VERSION 5.8 ;
BUSBITCHARS "[]" ;
DIVIDERCHAR "/" ;
UNITS
    DATABASE MICRONS 1000 ;
END UNITS

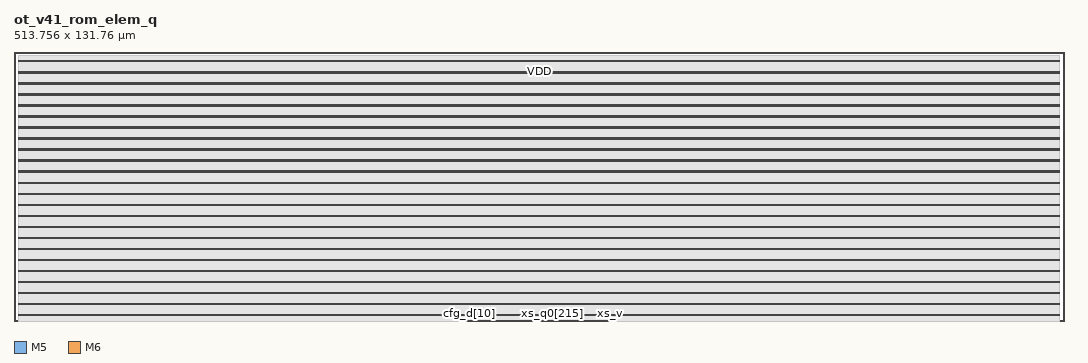
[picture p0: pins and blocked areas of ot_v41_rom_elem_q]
MACRO ot_v41_rom_elem_q
  FOREIGN ot_v41_rom_elem_q 0 0 ;
  CLASS BLOCK ;
  SIZE 513.756 BY 131.76 ;
  PIN busy
    DIRECTION OUTPUT ;
    USE SIGNAL ;
    PORT
      LAYER M5 ;
        RECT  221.568 0 221.592 0.084 ;
    END
  END busy
  PIN cfg_a[0]
    DIRECTION INPUT ;
    USE SIGNAL ;
    PORT
      LAYER M5 ;
        RECT  221.664 0 221.688 0.084 ;
    END
  END cfg_a[0]
  PIN cfg_a[1]
    DIRECTION INPUT ;
    USE SIGNAL ;
    PORT
      LAYER M5 ;
        RECT  221.76 0 221.784 0.084 ;
    END
  END cfg_a[1]
  PIN cfg_a[2]
    DIRECTION INPUT ;
    USE SIGNAL ;
    PORT
      LAYER M5 ;
        RECT  221.856 0 221.88 0.084 ;
    END
  END cfg_a[2]
  PIN cfg_a[3]
    DIRECTION INPUT ;
    USE SIGNAL ;
    PORT
      LAYER M5 ;
        RECT  221.952 0 221.976 0.084 ;
    END
  END cfg_a[3]
  PIN cfg_a[4]
    DIRECTION INPUT ;
    USE SIGNAL ;
    PORT
      LAYER M5 ;
        RECT  222.048 0 222.072 0.084 ;
    END
  END cfg_a[4]
  PIN cfg_d[0]
    DIRECTION INPUT ;
    USE SIGNAL ;
    PORT
      LAYER M5 ;
        RECT  222.144 0 222.168 0.084 ;
    END
  END cfg_d[0]
  PIN cfg_d[10]
    DIRECTION INPUT ;
    USE SIGNAL ;
    PORT
      LAYER M5 ;
        RECT  223.104 0 223.128 0.084 ;
    END
  END cfg_d[10]
  PIN cfg_d[11]
    DIRECTION INPUT ;
    USE SIGNAL ;
    PORT
      LAYER M5 ;
        RECT  223.2 0 223.224 0.084 ;
    END
  END cfg_d[11]
  PIN cfg_d[12]
    DIRECTION INPUT ;
    USE SIGNAL ;
    PORT
      LAYER M5 ;
        RECT  223.296 0 223.32 0.084 ;
    END
  END cfg_d[12]
  PIN cfg_d[13]
    DIRECTION INPUT ;
    USE SIGNAL ;
    PORT
      LAYER M5 ;
        RECT  223.392 0 223.416 0.084 ;
    END
  END cfg_d[13]
  PIN cfg_d[14]
    DIRECTION INPUT ;
    USE SIGNAL ;
    PORT
      LAYER M5 ;
        RECT  223.488 0 223.512 0.084 ;
    END
  END cfg_d[14]
  PIN cfg_d[15]
    DIRECTION INPUT ;
    USE SIGNAL ;
    PORT
      LAYER M5 ;
        RECT  223.584 0 223.608 0.084 ;
    END
  END cfg_d[15]
  PIN cfg_d[16]
    DIRECTION INPUT ;
    USE SIGNAL ;
    PORT
      LAYER M5 ;
        RECT  223.68 0 223.704 0.084 ;
    END
  END cfg_d[16]
  PIN cfg_d[17]
    DIRECTION INPUT ;
    USE SIGNAL ;
    PORT
      LAYER M5 ;
        RECT  223.776 0 223.8 0.084 ;
    END
  END cfg_d[17]
  PIN cfg_d[18]
    DIRECTION INPUT ;
    USE SIGNAL ;
    PORT
      LAYER M5 ;
        RECT  223.872 0 223.896 0.084 ;
    END
  END cfg_d[18]
  PIN cfg_d[19]
    DIRECTION INPUT ;
    USE SIGNAL ;
    PORT
      LAYER M5 ;
        RECT  223.968 0 223.992 0.084 ;
    END
  END cfg_d[19]
  PIN cfg_d[1]
    DIRECTION INPUT ;
    USE SIGNAL ;
    PORT
      LAYER M5 ;
        RECT  222.24 0 222.264 0.084 ;
    END
  END cfg_d[1]
  PIN cfg_d[20]
    DIRECTION INPUT ;
    USE SIGNAL ;
    PORT
      LAYER M5 ;
        RECT  224.064 0 224.088 0.084 ;
    END
  END cfg_d[20]
  PIN cfg_d[21]
    DIRECTION INPUT ;
    USE SIGNAL ;
    PORT
      LAYER M5 ;
        RECT  224.16 0 224.184 0.084 ;
    END
  END cfg_d[21]
  PIN cfg_d[22]
    DIRECTION INPUT ;
    USE SIGNAL ;
    PORT
      LAYER M5 ;
        RECT  224.256 0 224.28 0.084 ;
    END
  END cfg_d[22]
  PIN cfg_d[23]
    DIRECTION INPUT ;
    USE SIGNAL ;
    PORT
      LAYER M5 ;
        RECT  224.352 0 224.376 0.084 ;
    END
  END cfg_d[23]
  PIN cfg_d[24]
    DIRECTION INPUT ;
    USE SIGNAL ;
    PORT
      LAYER M5 ;
        RECT  224.448 0 224.472 0.084 ;
    END
  END cfg_d[24]
  PIN cfg_d[25]
    DIRECTION INPUT ;
    USE SIGNAL ;
    PORT
      LAYER M5 ;
        RECT  224.544 0 224.568 0.084 ;
    END
  END cfg_d[25]
  PIN cfg_d[26]
    DIRECTION INPUT ;
    USE SIGNAL ;
    PORT
      LAYER M5 ;
        RECT  224.64 0 224.664 0.084 ;
    END
  END cfg_d[26]
  PIN cfg_d[27]
    DIRECTION INPUT ;
    USE SIGNAL ;
    PORT
      LAYER M5 ;
        RECT  224.736 0 224.76 0.084 ;
    END
  END cfg_d[27]
  PIN cfg_d[28]
    DIRECTION INPUT ;
    USE SIGNAL ;
    PORT
      LAYER M5 ;
        RECT  224.832 0 224.856 0.084 ;
    END
  END cfg_d[28]
  PIN cfg_d[29]
    DIRECTION INPUT ;
    USE SIGNAL ;
    PORT
      LAYER M5 ;
        RECT  224.928 0 224.952 0.084 ;
    END
  END cfg_d[29]
  PIN cfg_d[2]
    DIRECTION INPUT ;
    USE SIGNAL ;
    PORT
      LAYER M5 ;
        RECT  222.336 0 222.36 0.084 ;
    END
  END cfg_d[2]
  PIN cfg_d[30]
    DIRECTION INPUT ;
    USE SIGNAL ;
    PORT
      LAYER M5 ;
        RECT  225.024 0 225.048 0.084 ;
    END
  END cfg_d[30]
  PIN cfg_d[31]
    DIRECTION INPUT ;
    USE SIGNAL ;
    PORT
      LAYER M5 ;
        RECT  225.12 0 225.144 0.084 ;
    END
  END cfg_d[31]
  PIN cfg_d[32]
    DIRECTION INPUT ;
    USE SIGNAL ;
    PORT
      LAYER M5 ;
        RECT  225.216 0 225.24 0.084 ;
    END
  END cfg_d[32]
  PIN cfg_d[33]
    DIRECTION INPUT ;
    USE SIGNAL ;
    PORT
      LAYER M5 ;
        RECT  225.312 0 225.336 0.084 ;
    END
  END cfg_d[33]
  PIN cfg_d[34]
    DIRECTION INPUT ;
    USE SIGNAL ;
    PORT
      LAYER M5 ;
        RECT  225.408 0 225.432 0.084 ;
    END
  END cfg_d[34]
  PIN cfg_d[35]
    DIRECTION INPUT ;
    USE SIGNAL ;
    PORT
      LAYER M5 ;
        RECT  225.504 0 225.528 0.084 ;
    END
  END cfg_d[35]
  PIN cfg_d[36]
    DIRECTION INPUT ;
    USE SIGNAL ;
    PORT
      LAYER M5 ;
        RECT  225.6 0 225.624 0.084 ;
    END
  END cfg_d[36]
  PIN cfg_d[37]
    DIRECTION INPUT ;
    USE SIGNAL ;
    PORT
      LAYER M5 ;
        RECT  225.696 0 225.72 0.084 ;
    END
  END cfg_d[37]
  PIN cfg_d[38]
    DIRECTION INPUT ;
    USE SIGNAL ;
    PORT
      LAYER M5 ;
        RECT  225.792 0 225.816 0.084 ;
    END
  END cfg_d[38]
  PIN cfg_d[39]
    DIRECTION INPUT ;
    USE SIGNAL ;
    PORT
      LAYER M5 ;
        RECT  225.888 0 225.912 0.084 ;
    END
  END cfg_d[39]
  PIN cfg_d[3]
    DIRECTION INPUT ;
    USE SIGNAL ;
    PORT
      LAYER M5 ;
        RECT  222.432 0 222.456 0.084 ;
    END
  END cfg_d[3]
  PIN cfg_d[40]
    DIRECTION INPUT ;
    USE SIGNAL ;
    PORT
      LAYER M5 ;
        RECT  225.984 0 226.008 0.084 ;
    END
  END cfg_d[40]
  PIN cfg_d[41]
    DIRECTION INPUT ;
    USE SIGNAL ;
    PORT
      LAYER M5 ;
        RECT  226.08 0 226.104 0.084 ;
    END
  END cfg_d[41]
  PIN cfg_d[42]
    DIRECTION INPUT ;
    USE SIGNAL ;
    PORT
      LAYER M5 ;
        RECT  226.176 0 226.2 0.084 ;
    END
  END cfg_d[42]
  PIN cfg_d[43]
    DIRECTION INPUT ;
    USE SIGNAL ;
    PORT
      LAYER M5 ;
        RECT  226.272 0 226.296 0.084 ;
    END
  END cfg_d[43]
  PIN cfg_d[44]
    DIRECTION INPUT ;
    USE SIGNAL ;
    PORT
      LAYER M5 ;
        RECT  226.368 0 226.392 0.084 ;
    END
  END cfg_d[44]
  PIN cfg_d[45]
    DIRECTION INPUT ;
    USE SIGNAL ;
    PORT
      LAYER M5 ;
        RECT  226.464 0 226.488 0.084 ;
    END
  END cfg_d[45]
  PIN cfg_d[46]
    DIRECTION INPUT ;
    USE SIGNAL ;
    PORT
      LAYER M5 ;
        RECT  226.56 0 226.584 0.084 ;
    END
  END cfg_d[46]
  PIN cfg_d[47]
    DIRECTION INPUT ;
    USE SIGNAL ;
    PORT
      LAYER M5 ;
        RECT  226.656 0 226.68 0.084 ;
    END
  END cfg_d[47]
  PIN cfg_d[4]
    DIRECTION INPUT ;
    USE SIGNAL ;
    PORT
      LAYER M5 ;
        RECT  222.528 0 222.552 0.084 ;
    END
  END cfg_d[4]
  PIN cfg_d[5]
    DIRECTION INPUT ;
    USE SIGNAL ;
    PORT
      LAYER M5 ;
        RECT  222.624 0 222.648 0.084 ;
    END
  END cfg_d[5]
  PIN cfg_d[6]
    DIRECTION INPUT ;
    USE SIGNAL ;
    PORT
      LAYER M5 ;
        RECT  222.72 0 222.744 0.084 ;
    END
  END cfg_d[6]
  PIN cfg_d[7]
    DIRECTION INPUT ;
    USE SIGNAL ;
    PORT
      LAYER M5 ;
        RECT  222.816 0 222.84 0.084 ;
    END
  END cfg_d[7]
  PIN cfg_d[8]
    DIRECTION INPUT ;
    USE SIGNAL ;
    PORT
      LAYER M5 ;
        RECT  222.912 0 222.936 0.084 ;
    END
  END cfg_d[8]
  PIN cfg_d[9]
    DIRECTION INPUT ;
    USE SIGNAL ;
    PORT
      LAYER M5 ;
        RECT  223.008 0 223.032 0.084 ;
    END
  END cfg_d[9]
  PIN cfg_v
    DIRECTION INPUT ;
    USE SIGNAL ;
    PORT
      LAYER M5 ;
        RECT  226.752 0 226.776 0.084 ;
    END
  END cfg_v
  PIN clk
    DIRECTION INPUT ;
    USE SIGNAL ;
    PORT
      LAYER M5 ;
        RECT  226.848 0 226.872 0.084 ;
    END
  END clk
  PIN fault
    DIRECTION OUTPUT ;
    USE SIGNAL ;
    PORT
      LAYER M5 ;
        RECT  226.944 0 226.968 0.084 ;
    END
  END fault
  PIN go
    DIRECTION INPUT ;
    USE SIGNAL ;
    PORT
      LAYER M5 ;
        RECT  227.04 0 227.064 0.084 ;
    END
  END go
  PIN perr[0]
    DIRECTION OUTPUT ;
    USE SIGNAL ;
    PORT
      LAYER M5 ;
        RECT  227.136 0 227.16 0.084 ;
    END
  END perr[0]
  PIN perr[1]
    DIRECTION OUTPUT ;
    USE SIGNAL ;
    PORT
      LAYER M5 ;
        RECT  227.232 0 227.256 0.084 ;
    END
  END perr[1]
  PIN pnseg[0]
    DIRECTION OUTPUT ;
    USE SIGNAL ;
    PORT
      LAYER M5 ;
        RECT  227.328 0 227.352 0.084 ;
    END
  END pnseg[0]
  PIN pnseg[1]
    DIRECTION OUTPUT ;
    USE SIGNAL ;
    PORT
      LAYER M5 ;
        RECT  227.424 0 227.448 0.084 ;
    END
  END pnseg[1]
  PIN pnseg[2]
    DIRECTION OUTPUT ;
    USE SIGNAL ;
    PORT
      LAYER M5 ;
        RECT  227.52 0 227.544 0.084 ;
    END
  END pnseg[2]
  PIN pnseg[3]
    DIRECTION OUTPUT ;
    USE SIGNAL ;
    PORT
      LAYER M5 ;
        RECT  227.616 0 227.64 0.084 ;
    END
  END pnseg[3]
  PIN pnseg[4]
    DIRECTION OUTPUT ;
    USE SIGNAL ;
    PORT
      LAYER M5 ;
        RECT  227.712 0 227.736 0.084 ;
    END
  END pnseg[4]
  PIN pnseg[5]
    DIRECTION OUTPUT ;
    USE SIGNAL ;
    PORT
      LAYER M5 ;
        RECT  227.808 0 227.832 0.084 ;
    END
  END pnseg[5]
  PIN pnseg[6]
    DIRECTION OUTPUT ;
    USE SIGNAL ;
    PORT
      LAYER M5 ;
        RECT  227.904 0 227.928 0.084 ;
    END
  END pnseg[6]
  PIN pnseg[7]
    DIRECTION OUTPUT ;
    USE SIGNAL ;
    PORT
      LAYER M5 ;
        RECT  228 0 228.024 0.084 ;
    END
  END pnseg[7]
  PIN pnseg[8]
    DIRECTION OUTPUT ;
    USE SIGNAL ;
    PORT
      LAYER M5 ;
        RECT  228.096 0 228.12 0.084 ;
    END
  END pnseg[8]
  PIN pnseg[9]
    DIRECTION OUTPUT ;
    USE SIGNAL ;
    PORT
      LAYER M5 ;
        RECT  228.192 0 228.216 0.084 ;
    END
  END pnseg[9]
  PIN ppos[0]
    DIRECTION OUTPUT ;
    USE SIGNAL ;
    PORT
      LAYER M5 ;
        RECT  228.288 0 228.312 0.084 ;
    END
  END ppos[0]
  PIN ppos[1]
    DIRECTION OUTPUT ;
    USE SIGNAL ;
    PORT
      LAYER M5 ;
        RECT  228.384 0 228.408 0.084 ;
    END
  END ppos[1]
  PIN ppos[2]
    DIRECTION OUTPUT ;
    USE SIGNAL ;
    PORT
      LAYER M5 ;
        RECT  228.48 0 228.504 0.084 ;
    END
  END ppos[2]
  PIN ppos[3]
    DIRECTION OUTPUT ;
    USE SIGNAL ;
    PORT
      LAYER M5 ;
        RECT  228.576 0 228.6 0.084 ;
    END
  END ppos[3]
  PIN ppos[4]
    DIRECTION OUTPUT ;
    USE SIGNAL ;
    PORT
      LAYER M5 ;
        RECT  228.672 0 228.696 0.084 ;
    END
  END ppos[4]
  PIN ppos[5]
    DIRECTION OUTPUT ;
    USE SIGNAL ;
    PORT
      LAYER M5 ;
        RECT  228.768 0 228.792 0.084 ;
    END
  END ppos[5]
  PIN prow[0]
    DIRECTION OUTPUT ;
    USE SIGNAL ;
    PORT
      LAYER M5 ;
        RECT  228.864 0 228.888 0.084 ;
    END
  END prow[0]
  PIN prow[10]
    DIRECTION OUTPUT ;
    USE SIGNAL ;
    PORT
      LAYER M5 ;
        RECT  229.824 0 229.848 0.084 ;
    END
  END prow[10]
  PIN prow[11]
    DIRECTION OUTPUT ;
    USE SIGNAL ;
    PORT
      LAYER M5 ;
        RECT  229.92 0 229.944 0.084 ;
    END
  END prow[11]
  PIN prow[12]
    DIRECTION OUTPUT ;
    USE SIGNAL ;
    PORT
      LAYER M5 ;
        RECT  230.016 0 230.04 0.084 ;
    END
  END prow[12]
  PIN prow[13]
    DIRECTION OUTPUT ;
    USE SIGNAL ;
    PORT
      LAYER M5 ;
        RECT  230.112 0 230.136 0.084 ;
    END
  END prow[13]
  PIN prow[14]
    DIRECTION OUTPUT ;
    USE SIGNAL ;
    PORT
      LAYER M5 ;
        RECT  230.208 0 230.232 0.084 ;
    END
  END prow[14]
  PIN prow[15]
    DIRECTION OUTPUT ;
    USE SIGNAL ;
    PORT
      LAYER M5 ;
        RECT  230.304 0 230.328 0.084 ;
    END
  END prow[15]
  PIN prow[16]
    DIRECTION OUTPUT ;
    USE SIGNAL ;
    PORT
      LAYER M5 ;
        RECT  230.4 0 230.424 0.084 ;
    END
  END prow[16]
  PIN prow[17]
    DIRECTION OUTPUT ;
    USE SIGNAL ;
    PORT
      LAYER M5 ;
        RECT  230.496 0 230.52 0.084 ;
    END
  END prow[17]
  PIN prow[18]
    DIRECTION OUTPUT ;
    USE SIGNAL ;
    PORT
      LAYER M5 ;
        RECT  230.592 0 230.616 0.084 ;
    END
  END prow[18]
  PIN prow[19]
    DIRECTION OUTPUT ;
    USE SIGNAL ;
    PORT
      LAYER M5 ;
        RECT  230.688 0 230.712 0.084 ;
    END
  END prow[19]
  PIN prow[1]
    DIRECTION OUTPUT ;
    USE SIGNAL ;
    PORT
      LAYER M5 ;
        RECT  228.96 0 228.984 0.084 ;
    END
  END prow[1]
  PIN prow[20]
    DIRECTION OUTPUT ;
    USE SIGNAL ;
    PORT
      LAYER M5 ;
        RECT  230.784 0 230.808 0.084 ;
    END
  END prow[20]
  PIN prow[21]
    DIRECTION OUTPUT ;
    USE SIGNAL ;
    PORT
      LAYER M5 ;
        RECT  230.88 0 230.904 0.084 ;
    END
  END prow[21]
  PIN prow[22]
    DIRECTION OUTPUT ;
    USE SIGNAL ;
    PORT
      LAYER M5 ;
        RECT  230.976 0 231 0.084 ;
    END
  END prow[22]
  PIN prow[23]
    DIRECTION OUTPUT ;
    USE SIGNAL ;
    PORT
      LAYER M5 ;
        RECT  231.072 0 231.096 0.084 ;
    END
  END prow[23]
  PIN prow[24]
    DIRECTION OUTPUT ;
    USE SIGNAL ;
    PORT
      LAYER M5 ;
        RECT  231.168 0 231.192 0.084 ;
    END
  END prow[24]
  PIN prow[25]
    DIRECTION OUTPUT ;
    USE SIGNAL ;
    PORT
      LAYER M5 ;
        RECT  231.264 0 231.288 0.084 ;
    END
  END prow[25]
  PIN prow[26]
    DIRECTION OUTPUT ;
    USE SIGNAL ;
    PORT
      LAYER M5 ;
        RECT  231.36 0 231.384 0.084 ;
    END
  END prow[26]
  PIN prow[27]
    DIRECTION OUTPUT ;
    USE SIGNAL ;
    PORT
      LAYER M5 ;
        RECT  231.456 0 231.48 0.084 ;
    END
  END prow[27]
  PIN prow[28]
    DIRECTION OUTPUT ;
    USE SIGNAL ;
    PORT
      LAYER M5 ;
        RECT  231.552 0 231.576 0.084 ;
    END
  END prow[28]
  PIN prow[29]
    DIRECTION OUTPUT ;
    USE SIGNAL ;
    PORT
      LAYER M5 ;
        RECT  231.648 0 231.672 0.084 ;
    END
  END prow[29]
  PIN prow[2]
    DIRECTION OUTPUT ;
    USE SIGNAL ;
    PORT
      LAYER M5 ;
        RECT  229.056 0 229.08 0.084 ;
    END
  END prow[2]
  PIN prow[30]
    DIRECTION OUTPUT ;
    USE SIGNAL ;
    PORT
      LAYER M5 ;
        RECT  231.744 0 231.768 0.084 ;
    END
  END prow[30]
  PIN prow[31]
    DIRECTION OUTPUT ;
    USE SIGNAL ;
    PORT
      LAYER M5 ;
        RECT  231.84 0 231.864 0.084 ;
    END
  END prow[31]
  PIN prow[3]
    DIRECTION OUTPUT ;
    USE SIGNAL ;
    PORT
      LAYER M5 ;
        RECT  229.152 0 229.176 0.084 ;
    END
  END prow[3]
  PIN prow[4]
    DIRECTION OUTPUT ;
    USE SIGNAL ;
    PORT
      LAYER M5 ;
        RECT  229.248 0 229.272 0.084 ;
    END
  END prow[4]
  PIN prow[5]
    DIRECTION OUTPUT ;
    USE SIGNAL ;
    PORT
      LAYER M5 ;
        RECT  229.344 0 229.368 0.084 ;
    END
  END prow[5]
  PIN prow[6]
    DIRECTION OUTPUT ;
    USE SIGNAL ;
    PORT
      LAYER M5 ;
        RECT  229.44 0 229.464 0.084 ;
    END
  END prow[6]
  PIN prow[7]
    DIRECTION OUTPUT ;
    USE SIGNAL ;
    PORT
      LAYER M5 ;
        RECT  229.536 0 229.56 0.084 ;
    END
  END prow[7]
  PIN prow[8]
    DIRECTION OUTPUT ;
    USE SIGNAL ;
    PORT
      LAYER M5 ;
        RECT  229.632 0 229.656 0.084 ;
    END
  END prow[8]
  PIN prow[9]
    DIRECTION OUTPUT ;
    USE SIGNAL ;
    PORT
      LAYER M5 ;
        RECT  229.728 0 229.752 0.084 ;
    END
  END prow[9]
  PIN pseg[0]
    DIRECTION OUTPUT ;
    USE SIGNAL ;
    PORT
      LAYER M5 ;
        RECT  231.936 0 231.96 0.084 ;
    END
  END pseg[0]
  PIN pseg[1]
    DIRECTION OUTPUT ;
    USE SIGNAL ;
    PORT
      LAYER M5 ;
        RECT  232.032 0 232.056 0.084 ;
    END
  END pseg[1]
  PIN pseg[2]
    DIRECTION OUTPUT ;
    USE SIGNAL ;
    PORT
      LAYER M5 ;
        RECT  232.128 0 232.152 0.084 ;
    END
  END pseg[2]
  PIN pseg[3]
    DIRECTION OUTPUT ;
    USE SIGNAL ;
    PORT
      LAYER M5 ;
        RECT  232.224 0 232.248 0.084 ;
    END
  END pseg[3]
  PIN pseg[4]
    DIRECTION OUTPUT ;
    USE SIGNAL ;
    PORT
      LAYER M5 ;
        RECT  232.32 0 232.344 0.084 ;
    END
  END pseg[4]
  PIN pseg[5]
    DIRECTION OUTPUT ;
    USE SIGNAL ;
    PORT
      LAYER M5 ;
        RECT  232.416 0 232.44 0.084 ;
    END
  END pseg[5]
  PIN pseg[6]
    DIRECTION OUTPUT ;
    USE SIGNAL ;
    PORT
      LAYER M5 ;
        RECT  232.512 0 232.536 0.084 ;
    END
  END pseg[6]
  PIN pseg[7]
    DIRECTION OUTPUT ;
    USE SIGNAL ;
    PORT
      LAYER M5 ;
        RECT  232.608 0 232.632 0.084 ;
    END
  END pseg[7]
  PIN pseg[8]
    DIRECTION OUTPUT ;
    USE SIGNAL ;
    PORT
      LAYER M5 ;
        RECT  232.704 0 232.728 0.084 ;
    END
  END pseg[8]
  PIN pseg[9]
    DIRECTION OUTPUT ;
    USE SIGNAL ;
    PORT
      LAYER M5 ;
        RECT  232.8 0 232.824 0.084 ;
    END
  END pseg[9]
  PIN pv[0]
    DIRECTION OUTPUT ;
    USE SIGNAL ;
    PORT
      LAYER M5 ;
        RECT  232.896 0 232.92 0.084 ;
    END
  END pv[0]
  PIN pv[1]
    DIRECTION OUTPUT ;
    USE SIGNAL ;
    PORT
      LAYER M5 ;
        RECT  232.992 0 233.016 0.084 ;
    END
  END pv[1]
  PIN pval[0]
    DIRECTION OUTPUT ;
    USE SIGNAL ;
    PORT
      LAYER M5 ;
        RECT  233.088 0 233.112 0.084 ;
    END
  END pval[0]
  PIN pval[10]
    DIRECTION OUTPUT ;
    USE SIGNAL ;
    PORT
      LAYER M5 ;
        RECT  234.048 0 234.072 0.084 ;
    END
  END pval[10]
  PIN pval[11]
    DIRECTION OUTPUT ;
    USE SIGNAL ;
    PORT
      LAYER M5 ;
        RECT  234.144 0 234.168 0.084 ;
    END
  END pval[11]
  PIN pval[12]
    DIRECTION OUTPUT ;
    USE SIGNAL ;
    PORT
      LAYER M5 ;
        RECT  234.24 0 234.264 0.084 ;
    END
  END pval[12]
  PIN pval[13]
    DIRECTION OUTPUT ;
    USE SIGNAL ;
    PORT
      LAYER M5 ;
        RECT  234.336 0 234.36 0.084 ;
    END
  END pval[13]
  PIN pval[14]
    DIRECTION OUTPUT ;
    USE SIGNAL ;
    PORT
      LAYER M5 ;
        RECT  234.432 0 234.456 0.084 ;
    END
  END pval[14]
  PIN pval[15]
    DIRECTION OUTPUT ;
    USE SIGNAL ;
    PORT
      LAYER M5 ;
        RECT  234.528 0 234.552 0.084 ;
    END
  END pval[15]
  PIN pval[16]
    DIRECTION OUTPUT ;
    USE SIGNAL ;
    PORT
      LAYER M5 ;
        RECT  234.624 0 234.648 0.084 ;
    END
  END pval[16]
  PIN pval[17]
    DIRECTION OUTPUT ;
    USE SIGNAL ;
    PORT
      LAYER M5 ;
        RECT  234.72 0 234.744 0.084 ;
    END
  END pval[17]
  PIN pval[18]
    DIRECTION OUTPUT ;
    USE SIGNAL ;
    PORT
      LAYER M5 ;
        RECT  234.816 0 234.84 0.084 ;
    END
  END pval[18]
  PIN pval[19]
    DIRECTION OUTPUT ;
    USE SIGNAL ;
    PORT
      LAYER M5 ;
        RECT  234.912 0 234.936 0.084 ;
    END
  END pval[19]
  PIN pval[1]
    DIRECTION OUTPUT ;
    USE SIGNAL ;
    PORT
      LAYER M5 ;
        RECT  233.184 0 233.208 0.084 ;
    END
  END pval[1]
  PIN pval[20]
    DIRECTION OUTPUT ;
    USE SIGNAL ;
    PORT
      LAYER M5 ;
        RECT  235.008 0 235.032 0.084 ;
    END
  END pval[20]
  PIN pval[21]
    DIRECTION OUTPUT ;
    USE SIGNAL ;
    PORT
      LAYER M5 ;
        RECT  235.104 0 235.128 0.084 ;
    END
  END pval[21]
  PIN pval[22]
    DIRECTION OUTPUT ;
    USE SIGNAL ;
    PORT
      LAYER M5 ;
        RECT  235.2 0 235.224 0.084 ;
    END
  END pval[22]
  PIN pval[23]
    DIRECTION OUTPUT ;
    USE SIGNAL ;
    PORT
      LAYER M5 ;
        RECT  235.296 0 235.32 0.084 ;
    END
  END pval[23]
  PIN pval[24]
    DIRECTION OUTPUT ;
    USE SIGNAL ;
    PORT
      LAYER M5 ;
        RECT  235.392 0 235.416 0.084 ;
    END
  END pval[24]
  PIN pval[25]
    DIRECTION OUTPUT ;
    USE SIGNAL ;
    PORT
      LAYER M5 ;
        RECT  235.488 0 235.512 0.084 ;
    END
  END pval[25]
  PIN pval[26]
    DIRECTION OUTPUT ;
    USE SIGNAL ;
    PORT
      LAYER M5 ;
        RECT  235.584 0 235.608 0.084 ;
    END
  END pval[26]
  PIN pval[27]
    DIRECTION OUTPUT ;
    USE SIGNAL ;
    PORT
      LAYER M5 ;
        RECT  235.68 0 235.704 0.084 ;
    END
  END pval[27]
  PIN pval[28]
    DIRECTION OUTPUT ;
    USE SIGNAL ;
    PORT
      LAYER M5 ;
        RECT  235.776 0 235.8 0.084 ;
    END
  END pval[28]
  PIN pval[29]
    DIRECTION OUTPUT ;
    USE SIGNAL ;
    PORT
      LAYER M5 ;
        RECT  235.872 0 235.896 0.084 ;
    END
  END pval[29]
  PIN pval[2]
    DIRECTION OUTPUT ;
    USE SIGNAL ;
    PORT
      LAYER M5 ;
        RECT  233.28 0 233.304 0.084 ;
    END
  END pval[2]
  PIN pval[30]
    DIRECTION OUTPUT ;
    USE SIGNAL ;
    PORT
      LAYER M5 ;
        RECT  235.968 0 235.992 0.084 ;
    END
  END pval[30]
  PIN pval[31]
    DIRECTION OUTPUT ;
    USE SIGNAL ;
    PORT
      LAYER M5 ;
        RECT  236.064 0 236.088 0.084 ;
    END
  END pval[31]
  PIN pval[32]
    DIRECTION OUTPUT ;
    USE SIGNAL ;
    PORT
      LAYER M5 ;
        RECT  236.16 0 236.184 0.084 ;
    END
  END pval[32]
  PIN pval[33]
    DIRECTION OUTPUT ;
    USE SIGNAL ;
    PORT
      LAYER M5 ;
        RECT  236.256 0 236.28 0.084 ;
    END
  END pval[33]
  PIN pval[34]
    DIRECTION OUTPUT ;
    USE SIGNAL ;
    PORT
      LAYER M5 ;
        RECT  236.352 0 236.376 0.084 ;
    END
  END pval[34]
  PIN pval[35]
    DIRECTION OUTPUT ;
    USE SIGNAL ;
    PORT
      LAYER M5 ;
        RECT  236.448 0 236.472 0.084 ;
    END
  END pval[35]
  PIN pval[36]
    DIRECTION OUTPUT ;
    USE SIGNAL ;
    PORT
      LAYER M5 ;
        RECT  236.544 0 236.568 0.084 ;
    END
  END pval[36]
  PIN pval[37]
    DIRECTION OUTPUT ;
    USE SIGNAL ;
    PORT
      LAYER M5 ;
        RECT  236.64 0 236.664 0.084 ;
    END
  END pval[37]
  PIN pval[38]
    DIRECTION OUTPUT ;
    USE SIGNAL ;
    PORT
      LAYER M5 ;
        RECT  236.736 0 236.76 0.084 ;
    END
  END pval[38]
  PIN pval[39]
    DIRECTION OUTPUT ;
    USE SIGNAL ;
    PORT
      LAYER M5 ;
        RECT  236.832 0 236.856 0.084 ;
    END
  END pval[39]
  PIN pval[3]
    DIRECTION OUTPUT ;
    USE SIGNAL ;
    PORT
      LAYER M5 ;
        RECT  233.376 0 233.4 0.084 ;
    END
  END pval[3]
  PIN pval[40]
    DIRECTION OUTPUT ;
    USE SIGNAL ;
    PORT
      LAYER M5 ;
        RECT  236.928 0 236.952 0.084 ;
    END
  END pval[40]
  PIN pval[41]
    DIRECTION OUTPUT ;
    USE SIGNAL ;
    PORT
      LAYER M5 ;
        RECT  237.024 0 237.048 0.084 ;
    END
  END pval[41]
  PIN pval[42]
    DIRECTION OUTPUT ;
    USE SIGNAL ;
    PORT
      LAYER M5 ;
        RECT  237.12 0 237.144 0.084 ;
    END
  END pval[42]
  PIN pval[43]
    DIRECTION OUTPUT ;
    USE SIGNAL ;
    PORT
      LAYER M5 ;
        RECT  237.216 0 237.24 0.084 ;
    END
  END pval[43]
  PIN pval[44]
    DIRECTION OUTPUT ;
    USE SIGNAL ;
    PORT
      LAYER M5 ;
        RECT  237.312 0 237.336 0.084 ;
    END
  END pval[44]
  PIN pval[45]
    DIRECTION OUTPUT ;
    USE SIGNAL ;
    PORT
      LAYER M5 ;
        RECT  237.408 0 237.432 0.084 ;
    END
  END pval[45]
  PIN pval[46]
    DIRECTION OUTPUT ;
    USE SIGNAL ;
    PORT
      LAYER M5 ;
        RECT  237.504 0 237.528 0.084 ;
    END
  END pval[46]
  PIN pval[47]
    DIRECTION OUTPUT ;
    USE SIGNAL ;
    PORT
      LAYER M5 ;
        RECT  237.6 0 237.624 0.084 ;
    END
  END pval[47]
  PIN pval[48]
    DIRECTION OUTPUT ;
    USE SIGNAL ;
    PORT
      LAYER M5 ;
        RECT  237.696 0 237.72 0.084 ;
    END
  END pval[48]
  PIN pval[49]
    DIRECTION OUTPUT ;
    USE SIGNAL ;
    PORT
      LAYER M5 ;
        RECT  237.792 0 237.816 0.084 ;
    END
  END pval[49]
  PIN pval[4]
    DIRECTION OUTPUT ;
    USE SIGNAL ;
    PORT
      LAYER M5 ;
        RECT  233.472 0 233.496 0.084 ;
    END
  END pval[4]
  PIN pval[50]
    DIRECTION OUTPUT ;
    USE SIGNAL ;
    PORT
      LAYER M5 ;
        RECT  237.888 0 237.912 0.084 ;
    END
  END pval[50]
  PIN pval[51]
    DIRECTION OUTPUT ;
    USE SIGNAL ;
    PORT
      LAYER M5 ;
        RECT  237.984 0 238.008 0.084 ;
    END
  END pval[51]
  PIN pval[52]
    DIRECTION OUTPUT ;
    USE SIGNAL ;
    PORT
      LAYER M5 ;
        RECT  238.08 0 238.104 0.084 ;
    END
  END pval[52]
  PIN pval[53]
    DIRECTION OUTPUT ;
    USE SIGNAL ;
    PORT
      LAYER M5 ;
        RECT  238.176 0 238.2 0.084 ;
    END
  END pval[53]
  PIN pval[54]
    DIRECTION OUTPUT ;
    USE SIGNAL ;
    PORT
      LAYER M5 ;
        RECT  238.272 0 238.296 0.084 ;
    END
  END pval[54]
  PIN pval[55]
    DIRECTION OUTPUT ;
    USE SIGNAL ;
    PORT
      LAYER M5 ;
        RECT  238.368 0 238.392 0.084 ;
    END
  END pval[55]
  PIN pval[56]
    DIRECTION OUTPUT ;
    USE SIGNAL ;
    PORT
      LAYER M5 ;
        RECT  238.464 0 238.488 0.084 ;
    END
  END pval[56]
  PIN pval[57]
    DIRECTION OUTPUT ;
    USE SIGNAL ;
    PORT
      LAYER M5 ;
        RECT  238.56 0 238.584 0.084 ;
    END
  END pval[57]
  PIN pval[58]
    DIRECTION OUTPUT ;
    USE SIGNAL ;
    PORT
      LAYER M5 ;
        RECT  238.656 0 238.68 0.084 ;
    END
  END pval[58]
  PIN pval[59]
    DIRECTION OUTPUT ;
    USE SIGNAL ;
    PORT
      LAYER M5 ;
        RECT  238.752 0 238.776 0.084 ;
    END
  END pval[59]
  PIN pval[5]
    DIRECTION OUTPUT ;
    USE SIGNAL ;
    PORT
      LAYER M5 ;
        RECT  233.568 0 233.592 0.084 ;
    END
  END pval[5]
  PIN pval[60]
    DIRECTION OUTPUT ;
    USE SIGNAL ;
    PORT
      LAYER M5 ;
        RECT  238.848 0 238.872 0.084 ;
    END
  END pval[60]
  PIN pval[61]
    DIRECTION OUTPUT ;
    USE SIGNAL ;
    PORT
      LAYER M5 ;
        RECT  238.944 0 238.968 0.084 ;
    END
  END pval[61]
  PIN pval[62]
    DIRECTION OUTPUT ;
    USE SIGNAL ;
    PORT
      LAYER M5 ;
        RECT  239.04 0 239.064 0.084 ;
    END
  END pval[62]
  PIN pval[63]
    DIRECTION OUTPUT ;
    USE SIGNAL ;
    PORT
      LAYER M5 ;
        RECT  239.136 0 239.16 0.084 ;
    END
  END pval[63]
  PIN pval[6]
    DIRECTION OUTPUT ;
    USE SIGNAL ;
    PORT
      LAYER M5 ;
        RECT  233.664 0 233.688 0.084 ;
    END
  END pval[6]
  PIN pval[7]
    DIRECTION OUTPUT ;
    USE SIGNAL ;
    PORT
      LAYER M5 ;
        RECT  233.76 0 233.784 0.084 ;
    END
  END pval[7]
  PIN pval[8]
    DIRECTION OUTPUT ;
    USE SIGNAL ;
    PORT
      LAYER M5 ;
        RECT  233.856 0 233.88 0.084 ;
    END
  END pval[8]
  PIN pval[9]
    DIRECTION OUTPUT ;
    USE SIGNAL ;
    PORT
      LAYER M5 ;
        RECT  233.952 0 233.976 0.084 ;
    END
  END pval[9]
  PIN rst_n
    DIRECTION INPUT ;
    USE SIGNAL ;
    PORT
      LAYER M5 ;
        RECT  239.232 0 239.256 0.084 ;
    END
  END rst_n
  PIN xs_b[0]
    DIRECTION INPUT ;
    USE SIGNAL ;
    PORT
      LAYER M5 ;
        RECT  239.328 0 239.352 0.084 ;
    END
  END xs_b[0]
  PIN xs_b[1]
    DIRECTION INPUT ;
    USE SIGNAL ;
    PORT
      LAYER M5 ;
        RECT  239.424 0 239.448 0.084 ;
    END
  END xs_b[1]
  PIN xs_b[2]
    DIRECTION INPUT ;
    USE SIGNAL ;
    PORT
      LAYER M5 ;
        RECT  239.52 0 239.544 0.084 ;
    END
  END xs_b[2]
  PIN xs_e0[0]
    DIRECTION INPUT ;
    USE SIGNAL ;
    PORT
      LAYER M5 ;
        RECT  239.616 0 239.64 0.084 ;
    END
  END xs_e0[0]
  PIN xs_e0[1]
    DIRECTION INPUT ;
    USE SIGNAL ;
    PORT
      LAYER M5 ;
        RECT  239.712 0 239.736 0.084 ;
    END
  END xs_e0[1]
  PIN xs_e0[2]
    DIRECTION INPUT ;
    USE SIGNAL ;
    PORT
      LAYER M5 ;
        RECT  239.808 0 239.832 0.084 ;
    END
  END xs_e0[2]
  PIN xs_e0[3]
    DIRECTION INPUT ;
    USE SIGNAL ;
    PORT
      LAYER M5 ;
        RECT  239.904 0 239.928 0.084 ;
    END
  END xs_e0[3]
  PIN xs_e0[4]
    DIRECTION INPUT ;
    USE SIGNAL ;
    PORT
      LAYER M5 ;
        RECT  240 0 240.024 0.084 ;
    END
  END xs_e0[4]
  PIN xs_e0[5]
    DIRECTION INPUT ;
    USE SIGNAL ;
    PORT
      LAYER M5 ;
        RECT  240.096 0 240.12 0.084 ;
    END
  END xs_e0[5]
  PIN xs_e0[6]
    DIRECTION INPUT ;
    USE SIGNAL ;
    PORT
      LAYER M5 ;
        RECT  240.192 0 240.216 0.084 ;
    END
  END xs_e0[6]
  PIN xs_e0[7]
    DIRECTION INPUT ;
    USE SIGNAL ;
    PORT
      LAYER M5 ;
        RECT  240.288 0 240.312 0.084 ;
    END
  END xs_e0[7]
  PIN xs_e0[8]
    DIRECTION INPUT ;
    USE SIGNAL ;
    PORT
      LAYER M5 ;
        RECT  240.384 0 240.408 0.084 ;
    END
  END xs_e0[8]
  PIN xs_e0[9]
    DIRECTION INPUT ;
    USE SIGNAL ;
    PORT
      LAYER M5 ;
        RECT  240.48 0 240.504 0.084 ;
    END
  END xs_e0[9]
  PIN xs_e1[0]
    DIRECTION INPUT ;
    USE SIGNAL ;
    PORT
      LAYER M5 ;
        RECT  240.576 0 240.6 0.084 ;
    END
  END xs_e1[0]
  PIN xs_e1[1]
    DIRECTION INPUT ;
    USE SIGNAL ;
    PORT
      LAYER M5 ;
        RECT  240.672 0 240.696 0.084 ;
    END
  END xs_e1[1]
  PIN xs_e1[2]
    DIRECTION INPUT ;
    USE SIGNAL ;
    PORT
      LAYER M5 ;
        RECT  240.768 0 240.792 0.084 ;
    END
  END xs_e1[2]
  PIN xs_e1[3]
    DIRECTION INPUT ;
    USE SIGNAL ;
    PORT
      LAYER M5 ;
        RECT  240.864 0 240.888 0.084 ;
    END
  END xs_e1[3]
  PIN xs_e1[4]
    DIRECTION INPUT ;
    USE SIGNAL ;
    PORT
      LAYER M5 ;
        RECT  240.96 0 240.984 0.084 ;
    END
  END xs_e1[4]
  PIN xs_e1[5]
    DIRECTION INPUT ;
    USE SIGNAL ;
    PORT
      LAYER M5 ;
        RECT  241.056 0 241.08 0.084 ;
    END
  END xs_e1[5]
  PIN xs_e1[6]
    DIRECTION INPUT ;
    USE SIGNAL ;
    PORT
      LAYER M5 ;
        RECT  241.152 0 241.176 0.084 ;
    END
  END xs_e1[6]
  PIN xs_e1[7]
    DIRECTION INPUT ;
    USE SIGNAL ;
    PORT
      LAYER M5 ;
        RECT  241.248 0 241.272 0.084 ;
    END
  END xs_e1[7]
  PIN xs_e1[8]
    DIRECTION INPUT ;
    USE SIGNAL ;
    PORT
      LAYER M5 ;
        RECT  241.344 0 241.368 0.084 ;
    END
  END xs_e1[8]
  PIN xs_e1[9]
    DIRECTION INPUT ;
    USE SIGNAL ;
    PORT
      LAYER M5 ;
        RECT  241.44 0 241.464 0.084 ;
    END
  END xs_e1[9]
  PIN xs_p[0]
    DIRECTION INPUT ;
    USE SIGNAL ;
    PORT
      LAYER M5 ;
        RECT  241.536 0 241.56 0.084 ;
    END
  END xs_p[0]
  PIN xs_p[1]
    DIRECTION INPUT ;
    USE SIGNAL ;
    PORT
      LAYER M5 ;
        RECT  241.632 0 241.656 0.084 ;
    END
  END xs_p[1]
  PIN xs_p[2]
    DIRECTION INPUT ;
    USE SIGNAL ;
    PORT
      LAYER M5 ;
        RECT  241.728 0 241.752 0.084 ;
    END
  END xs_p[2]
  PIN xs_p[3]
    DIRECTION INPUT ;
    USE SIGNAL ;
    PORT
      LAYER M5 ;
        RECT  241.824 0 241.848 0.084 ;
    END
  END xs_p[3]
  PIN xs_p[4]
    DIRECTION INPUT ;
    USE SIGNAL ;
    PORT
      LAYER M5 ;
        RECT  241.92 0 241.944 0.084 ;
    END
  END xs_p[4]
  PIN xs_p[5]
    DIRECTION INPUT ;
    USE SIGNAL ;
    PORT
      LAYER M5 ;
        RECT  242.016 0 242.04 0.084 ;
    END
  END xs_p[5]
  PIN xs_p[6]
    DIRECTION INPUT ;
    USE SIGNAL ;
    PORT
      LAYER M5 ;
        RECT  242.112 0 242.136 0.084 ;
    END
  END xs_p[6]
  PIN xs_p[7]
    DIRECTION INPUT ;
    USE SIGNAL ;
    PORT
      LAYER M5 ;
        RECT  242.208 0 242.232 0.084 ;
    END
  END xs_p[7]
  PIN xs_pos[0]
    DIRECTION INPUT ;
    USE SIGNAL ;
    PORT
      LAYER M5 ;
        RECT  242.304 0 242.328 0.084 ;
    END
  END xs_pos[0]
  PIN xs_pos[1]
    DIRECTION INPUT ;
    USE SIGNAL ;
    PORT
      LAYER M5 ;
        RECT  242.4 0 242.424 0.084 ;
    END
  END xs_pos[1]
  PIN xs_pos[2]
    DIRECTION INPUT ;
    USE SIGNAL ;
    PORT
      LAYER M5 ;
        RECT  242.496 0 242.52 0.084 ;
    END
  END xs_pos[2]
  PIN xs_q0[0]
    DIRECTION INPUT ;
    USE SIGNAL ;
    PORT
      LAYER M5 ;
        RECT  242.592 0 242.616 0.084 ;
    END
  END xs_q0[0]
  PIN xs_q0[100]
    DIRECTION INPUT ;
    USE SIGNAL ;
    PORT
      LAYER M5 ;
        RECT  252.192 0 252.216 0.084 ;
    END
  END xs_q0[100]
  PIN xs_q0[101]
    DIRECTION INPUT ;
    USE SIGNAL ;
    PORT
      LAYER M5 ;
        RECT  252.288 0 252.312 0.084 ;
    END
  END xs_q0[101]
  PIN xs_q0[102]
    DIRECTION INPUT ;
    USE SIGNAL ;
    PORT
      LAYER M5 ;
        RECT  252.384 0 252.408 0.084 ;
    END
  END xs_q0[102]
  PIN xs_q0[103]
    DIRECTION INPUT ;
    USE SIGNAL ;
    PORT
      LAYER M5 ;
        RECT  252.48 0 252.504 0.084 ;
    END
  END xs_q0[103]
  PIN xs_q0[104]
    DIRECTION INPUT ;
    USE SIGNAL ;
    PORT
      LAYER M5 ;
        RECT  252.576 0 252.6 0.084 ;
    END
  END xs_q0[104]
  PIN xs_q0[105]
    DIRECTION INPUT ;
    USE SIGNAL ;
    PORT
      LAYER M5 ;
        RECT  252.672 0 252.696 0.084 ;
    END
  END xs_q0[105]
  PIN xs_q0[106]
    DIRECTION INPUT ;
    USE SIGNAL ;
    PORT
      LAYER M5 ;
        RECT  252.768 0 252.792 0.084 ;
    END
  END xs_q0[106]
  PIN xs_q0[107]
    DIRECTION INPUT ;
    USE SIGNAL ;
    PORT
      LAYER M5 ;
        RECT  252.864 0 252.888 0.084 ;
    END
  END xs_q0[107]
  PIN xs_q0[108]
    DIRECTION INPUT ;
    USE SIGNAL ;
    PORT
      LAYER M5 ;
        RECT  252.96 0 252.984 0.084 ;
    END
  END xs_q0[108]
  PIN xs_q0[109]
    DIRECTION INPUT ;
    USE SIGNAL ;
    PORT
      LAYER M5 ;
        RECT  253.056 0 253.08 0.084 ;
    END
  END xs_q0[109]
  PIN xs_q0[10]
    DIRECTION INPUT ;
    USE SIGNAL ;
    PORT
      LAYER M5 ;
        RECT  243.552 0 243.576 0.084 ;
    END
  END xs_q0[10]
  PIN xs_q0[110]
    DIRECTION INPUT ;
    USE SIGNAL ;
    PORT
      LAYER M5 ;
        RECT  253.152 0 253.176 0.084 ;
    END
  END xs_q0[110]
  PIN xs_q0[111]
    DIRECTION INPUT ;
    USE SIGNAL ;
    PORT
      LAYER M5 ;
        RECT  253.248 0 253.272 0.084 ;
    END
  END xs_q0[111]
  PIN xs_q0[112]
    DIRECTION INPUT ;
    USE SIGNAL ;
    PORT
      LAYER M5 ;
        RECT  253.344 0 253.368 0.084 ;
    END
  END xs_q0[112]
  PIN xs_q0[113]
    DIRECTION INPUT ;
    USE SIGNAL ;
    PORT
      LAYER M5 ;
        RECT  253.44 0 253.464 0.084 ;
    END
  END xs_q0[113]
  PIN xs_q0[114]
    DIRECTION INPUT ;
    USE SIGNAL ;
    PORT
      LAYER M5 ;
        RECT  253.536 0 253.56 0.084 ;
    END
  END xs_q0[114]
  PIN xs_q0[115]
    DIRECTION INPUT ;
    USE SIGNAL ;
    PORT
      LAYER M5 ;
        RECT  253.632 0 253.656 0.084 ;
    END
  END xs_q0[115]
  PIN xs_q0[116]
    DIRECTION INPUT ;
    USE SIGNAL ;
    PORT
      LAYER M5 ;
        RECT  253.728 0 253.752 0.084 ;
    END
  END xs_q0[116]
  PIN xs_q0[117]
    DIRECTION INPUT ;
    USE SIGNAL ;
    PORT
      LAYER M5 ;
        RECT  253.824 0 253.848 0.084 ;
    END
  END xs_q0[117]
  PIN xs_q0[118]
    DIRECTION INPUT ;
    USE SIGNAL ;
    PORT
      LAYER M5 ;
        RECT  253.92 0 253.944 0.084 ;
    END
  END xs_q0[118]
  PIN xs_q0[119]
    DIRECTION INPUT ;
    USE SIGNAL ;
    PORT
      LAYER M5 ;
        RECT  254.016 0 254.04 0.084 ;
    END
  END xs_q0[119]
  PIN xs_q0[11]
    DIRECTION INPUT ;
    USE SIGNAL ;
    PORT
      LAYER M5 ;
        RECT  243.648 0 243.672 0.084 ;
    END
  END xs_q0[11]
  PIN xs_q0[120]
    DIRECTION INPUT ;
    USE SIGNAL ;
    PORT
      LAYER M5 ;
        RECT  254.112 0 254.136 0.084 ;
    END
  END xs_q0[120]
  PIN xs_q0[121]
    DIRECTION INPUT ;
    USE SIGNAL ;
    PORT
      LAYER M5 ;
        RECT  254.208 0 254.232 0.084 ;
    END
  END xs_q0[121]
  PIN xs_q0[122]
    DIRECTION INPUT ;
    USE SIGNAL ;
    PORT
      LAYER M5 ;
        RECT  254.304 0 254.328 0.084 ;
    END
  END xs_q0[122]
  PIN xs_q0[123]
    DIRECTION INPUT ;
    USE SIGNAL ;
    PORT
      LAYER M5 ;
        RECT  254.4 0 254.424 0.084 ;
    END
  END xs_q0[123]
  PIN xs_q0[124]
    DIRECTION INPUT ;
    USE SIGNAL ;
    PORT
      LAYER M5 ;
        RECT  254.496 0 254.52 0.084 ;
    END
  END xs_q0[124]
  PIN xs_q0[125]
    DIRECTION INPUT ;
    USE SIGNAL ;
    PORT
      LAYER M5 ;
        RECT  254.592 0 254.616 0.084 ;
    END
  END xs_q0[125]
  PIN xs_q0[126]
    DIRECTION INPUT ;
    USE SIGNAL ;
    PORT
      LAYER M5 ;
        RECT  254.688 0 254.712 0.084 ;
    END
  END xs_q0[126]
  PIN xs_q0[127]
    DIRECTION INPUT ;
    USE SIGNAL ;
    PORT
      LAYER M5 ;
        RECT  254.784 0 254.808 0.084 ;
    END
  END xs_q0[127]
  PIN xs_q0[128]
    DIRECTION INPUT ;
    USE SIGNAL ;
    PORT
      LAYER M5 ;
        RECT  254.88 0 254.904 0.084 ;
    END
  END xs_q0[128]
  PIN xs_q0[129]
    DIRECTION INPUT ;
    USE SIGNAL ;
    PORT
      LAYER M5 ;
        RECT  254.976 0 255 0.084 ;
    END
  END xs_q0[129]
  PIN xs_q0[12]
    DIRECTION INPUT ;
    USE SIGNAL ;
    PORT
      LAYER M5 ;
        RECT  243.744 0 243.768 0.084 ;
    END
  END xs_q0[12]
  PIN xs_q0[130]
    DIRECTION INPUT ;
    USE SIGNAL ;
    PORT
      LAYER M5 ;
        RECT  255.072 0 255.096 0.084 ;
    END
  END xs_q0[130]
  PIN xs_q0[131]
    DIRECTION INPUT ;
    USE SIGNAL ;
    PORT
      LAYER M5 ;
        RECT  255.168 0 255.192 0.084 ;
    END
  END xs_q0[131]
  PIN xs_q0[132]
    DIRECTION INPUT ;
    USE SIGNAL ;
    PORT
      LAYER M5 ;
        RECT  255.264 0 255.288 0.084 ;
    END
  END xs_q0[132]
  PIN xs_q0[133]
    DIRECTION INPUT ;
    USE SIGNAL ;
    PORT
      LAYER M5 ;
        RECT  255.36 0 255.384 0.084 ;
    END
  END xs_q0[133]
  PIN xs_q0[134]
    DIRECTION INPUT ;
    USE SIGNAL ;
    PORT
      LAYER M5 ;
        RECT  255.456 0 255.48 0.084 ;
    END
  END xs_q0[134]
  PIN xs_q0[135]
    DIRECTION INPUT ;
    USE SIGNAL ;
    PORT
      LAYER M5 ;
        RECT  255.552 0 255.576 0.084 ;
    END
  END xs_q0[135]
  PIN xs_q0[136]
    DIRECTION INPUT ;
    USE SIGNAL ;
    PORT
      LAYER M5 ;
        RECT  255.648 0 255.672 0.084 ;
    END
  END xs_q0[136]
  PIN xs_q0[137]
    DIRECTION INPUT ;
    USE SIGNAL ;
    PORT
      LAYER M5 ;
        RECT  255.744 0 255.768 0.084 ;
    END
  END xs_q0[137]
  PIN xs_q0[138]
    DIRECTION INPUT ;
    USE SIGNAL ;
    PORT
      LAYER M5 ;
        RECT  255.84 0 255.864 0.084 ;
    END
  END xs_q0[138]
  PIN xs_q0[139]
    DIRECTION INPUT ;
    USE SIGNAL ;
    PORT
      LAYER M5 ;
        RECT  255.936 0 255.96 0.084 ;
    END
  END xs_q0[139]
  PIN xs_q0[13]
    DIRECTION INPUT ;
    USE SIGNAL ;
    PORT
      LAYER M5 ;
        RECT  243.84 0 243.864 0.084 ;
    END
  END xs_q0[13]
  PIN xs_q0[140]
    DIRECTION INPUT ;
    USE SIGNAL ;
    PORT
      LAYER M5 ;
        RECT  256.032 0 256.056 0.084 ;
    END
  END xs_q0[140]
  PIN xs_q0[141]
    DIRECTION INPUT ;
    USE SIGNAL ;
    PORT
      LAYER M5 ;
        RECT  256.128 0 256.152 0.084 ;
    END
  END xs_q0[141]
  PIN xs_q0[142]
    DIRECTION INPUT ;
    USE SIGNAL ;
    PORT
      LAYER M5 ;
        RECT  256.224 0 256.248 0.084 ;
    END
  END xs_q0[142]
  PIN xs_q0[143]
    DIRECTION INPUT ;
    USE SIGNAL ;
    PORT
      LAYER M5 ;
        RECT  256.32 0 256.344 0.084 ;
    END
  END xs_q0[143]
  PIN xs_q0[144]
    DIRECTION INPUT ;
    USE SIGNAL ;
    PORT
      LAYER M5 ;
        RECT  256.416 0 256.44 0.084 ;
    END
  END xs_q0[144]
  PIN xs_q0[145]
    DIRECTION INPUT ;
    USE SIGNAL ;
    PORT
      LAYER M5 ;
        RECT  256.512 0 256.536 0.084 ;
    END
  END xs_q0[145]
  PIN xs_q0[146]
    DIRECTION INPUT ;
    USE SIGNAL ;
    PORT
      LAYER M5 ;
        RECT  256.608 0 256.632 0.084 ;
    END
  END xs_q0[146]
  PIN xs_q0[147]
    DIRECTION INPUT ;
    USE SIGNAL ;
    PORT
      LAYER M5 ;
        RECT  256.704 0 256.728 0.084 ;
    END
  END xs_q0[147]
  PIN xs_q0[148]
    DIRECTION INPUT ;
    USE SIGNAL ;
    PORT
      LAYER M5 ;
        RECT  256.8 0 256.824 0.084 ;
    END
  END xs_q0[148]
  PIN xs_q0[149]
    DIRECTION INPUT ;
    USE SIGNAL ;
    PORT
      LAYER M5 ;
        RECT  256.896 0 256.92 0.084 ;
    END
  END xs_q0[149]
  PIN xs_q0[14]
    DIRECTION INPUT ;
    USE SIGNAL ;
    PORT
      LAYER M5 ;
        RECT  243.936 0 243.96 0.084 ;
    END
  END xs_q0[14]
  PIN xs_q0[150]
    DIRECTION INPUT ;
    USE SIGNAL ;
    PORT
      LAYER M5 ;
        RECT  256.992 0 257.016 0.084 ;
    END
  END xs_q0[150]
  PIN xs_q0[151]
    DIRECTION INPUT ;
    USE SIGNAL ;
    PORT
      LAYER M5 ;
        RECT  257.088 0 257.112 0.084 ;
    END
  END xs_q0[151]
  PIN xs_q0[152]
    DIRECTION INPUT ;
    USE SIGNAL ;
    PORT
      LAYER M5 ;
        RECT  257.184 0 257.208 0.084 ;
    END
  END xs_q0[152]
  PIN xs_q0[153]
    DIRECTION INPUT ;
    USE SIGNAL ;
    PORT
      LAYER M5 ;
        RECT  257.28 0 257.304 0.084 ;
    END
  END xs_q0[153]
  PIN xs_q0[154]
    DIRECTION INPUT ;
    USE SIGNAL ;
    PORT
      LAYER M5 ;
        RECT  257.376 0 257.4 0.084 ;
    END
  END xs_q0[154]
  PIN xs_q0[155]
    DIRECTION INPUT ;
    USE SIGNAL ;
    PORT
      LAYER M5 ;
        RECT  257.472 0 257.496 0.084 ;
    END
  END xs_q0[155]
  PIN xs_q0[156]
    DIRECTION INPUT ;
    USE SIGNAL ;
    PORT
      LAYER M5 ;
        RECT  257.568 0 257.592 0.084 ;
    END
  END xs_q0[156]
  PIN xs_q0[157]
    DIRECTION INPUT ;
    USE SIGNAL ;
    PORT
      LAYER M5 ;
        RECT  257.664 0 257.688 0.084 ;
    END
  END xs_q0[157]
  PIN xs_q0[158]
    DIRECTION INPUT ;
    USE SIGNAL ;
    PORT
      LAYER M5 ;
        RECT  257.76 0 257.784 0.084 ;
    END
  END xs_q0[158]
  PIN xs_q0[159]
    DIRECTION INPUT ;
    USE SIGNAL ;
    PORT
      LAYER M5 ;
        RECT  257.856 0 257.88 0.084 ;
    END
  END xs_q0[159]
  PIN xs_q0[15]
    DIRECTION INPUT ;
    USE SIGNAL ;
    PORT
      LAYER M5 ;
        RECT  244.032 0 244.056 0.084 ;
    END
  END xs_q0[15]
  PIN xs_q0[160]
    DIRECTION INPUT ;
    USE SIGNAL ;
    PORT
      LAYER M5 ;
        RECT  257.952 0 257.976 0.084 ;
    END
  END xs_q0[160]
  PIN xs_q0[161]
    DIRECTION INPUT ;
    USE SIGNAL ;
    PORT
      LAYER M5 ;
        RECT  258.048 0 258.072 0.084 ;
    END
  END xs_q0[161]
  PIN xs_q0[162]
    DIRECTION INPUT ;
    USE SIGNAL ;
    PORT
      LAYER M5 ;
        RECT  258.144 0 258.168 0.084 ;
    END
  END xs_q0[162]
  PIN xs_q0[163]
    DIRECTION INPUT ;
    USE SIGNAL ;
    PORT
      LAYER M5 ;
        RECT  258.24 0 258.264 0.084 ;
    END
  END xs_q0[163]
  PIN xs_q0[164]
    DIRECTION INPUT ;
    USE SIGNAL ;
    PORT
      LAYER M5 ;
        RECT  258.336 0 258.36 0.084 ;
    END
  END xs_q0[164]
  PIN xs_q0[165]
    DIRECTION INPUT ;
    USE SIGNAL ;
    PORT
      LAYER M5 ;
        RECT  258.432 0 258.456 0.084 ;
    END
  END xs_q0[165]
  PIN xs_q0[166]
    DIRECTION INPUT ;
    USE SIGNAL ;
    PORT
      LAYER M5 ;
        RECT  258.528 0 258.552 0.084 ;
    END
  END xs_q0[166]
  PIN xs_q0[167]
    DIRECTION INPUT ;
    USE SIGNAL ;
    PORT
      LAYER M5 ;
        RECT  258.624 0 258.648 0.084 ;
    END
  END xs_q0[167]
  PIN xs_q0[168]
    DIRECTION INPUT ;
    USE SIGNAL ;
    PORT
      LAYER M5 ;
        RECT  258.72 0 258.744 0.084 ;
    END
  END xs_q0[168]
  PIN xs_q0[169]
    DIRECTION INPUT ;
    USE SIGNAL ;
    PORT
      LAYER M5 ;
        RECT  258.816 0 258.84 0.084 ;
    END
  END xs_q0[169]
  PIN xs_q0[16]
    DIRECTION INPUT ;
    USE SIGNAL ;
    PORT
      LAYER M5 ;
        RECT  244.128 0 244.152 0.084 ;
    END
  END xs_q0[16]
  PIN xs_q0[170]
    DIRECTION INPUT ;
    USE SIGNAL ;
    PORT
      LAYER M5 ;
        RECT  258.912 0 258.936 0.084 ;
    END
  END xs_q0[170]
  PIN xs_q0[171]
    DIRECTION INPUT ;
    USE SIGNAL ;
    PORT
      LAYER M5 ;
        RECT  259.008 0 259.032 0.084 ;
    END
  END xs_q0[171]
  PIN xs_q0[172]
    DIRECTION INPUT ;
    USE SIGNAL ;
    PORT
      LAYER M5 ;
        RECT  259.104 0 259.128 0.084 ;
    END
  END xs_q0[172]
  PIN xs_q0[173]
    DIRECTION INPUT ;
    USE SIGNAL ;
    PORT
      LAYER M5 ;
        RECT  259.2 0 259.224 0.084 ;
    END
  END xs_q0[173]
  PIN xs_q0[174]
    DIRECTION INPUT ;
    USE SIGNAL ;
    PORT
      LAYER M5 ;
        RECT  259.296 0 259.32 0.084 ;
    END
  END xs_q0[174]
  PIN xs_q0[175]
    DIRECTION INPUT ;
    USE SIGNAL ;
    PORT
      LAYER M5 ;
        RECT  259.392 0 259.416 0.084 ;
    END
  END xs_q0[175]
  PIN xs_q0[176]
    DIRECTION INPUT ;
    USE SIGNAL ;
    PORT
      LAYER M5 ;
        RECT  259.488 0 259.512 0.084 ;
    END
  END xs_q0[176]
  PIN xs_q0[177]
    DIRECTION INPUT ;
    USE SIGNAL ;
    PORT
      LAYER M5 ;
        RECT  259.584 0 259.608 0.084 ;
    END
  END xs_q0[177]
  PIN xs_q0[178]
    DIRECTION INPUT ;
    USE SIGNAL ;
    PORT
      LAYER M5 ;
        RECT  259.68 0 259.704 0.084 ;
    END
  END xs_q0[178]
  PIN xs_q0[179]
    DIRECTION INPUT ;
    USE SIGNAL ;
    PORT
      LAYER M5 ;
        RECT  259.776 0 259.8 0.084 ;
    END
  END xs_q0[179]
  PIN xs_q0[17]
    DIRECTION INPUT ;
    USE SIGNAL ;
    PORT
      LAYER M5 ;
        RECT  244.224 0 244.248 0.084 ;
    END
  END xs_q0[17]
  PIN xs_q0[180]
    DIRECTION INPUT ;
    USE SIGNAL ;
    PORT
      LAYER M5 ;
        RECT  259.872 0 259.896 0.084 ;
    END
  END xs_q0[180]
  PIN xs_q0[181]
    DIRECTION INPUT ;
    USE SIGNAL ;
    PORT
      LAYER M5 ;
        RECT  259.968 0 259.992 0.084 ;
    END
  END xs_q0[181]
  PIN xs_q0[182]
    DIRECTION INPUT ;
    USE SIGNAL ;
    PORT
      LAYER M5 ;
        RECT  260.064 0 260.088 0.084 ;
    END
  END xs_q0[182]
  PIN xs_q0[183]
    DIRECTION INPUT ;
    USE SIGNAL ;
    PORT
      LAYER M5 ;
        RECT  260.16 0 260.184 0.084 ;
    END
  END xs_q0[183]
  PIN xs_q0[184]
    DIRECTION INPUT ;
    USE SIGNAL ;
    PORT
      LAYER M5 ;
        RECT  260.256 0 260.28 0.084 ;
    END
  END xs_q0[184]
  PIN xs_q0[185]
    DIRECTION INPUT ;
    USE SIGNAL ;
    PORT
      LAYER M5 ;
        RECT  260.352 0 260.376 0.084 ;
    END
  END xs_q0[185]
  PIN xs_q0[186]
    DIRECTION INPUT ;
    USE SIGNAL ;
    PORT
      LAYER M5 ;
        RECT  260.448 0 260.472 0.084 ;
    END
  END xs_q0[186]
  PIN xs_q0[187]
    DIRECTION INPUT ;
    USE SIGNAL ;
    PORT
      LAYER M5 ;
        RECT  260.544 0 260.568 0.084 ;
    END
  END xs_q0[187]
  PIN xs_q0[188]
    DIRECTION INPUT ;
    USE SIGNAL ;
    PORT
      LAYER M5 ;
        RECT  260.64 0 260.664 0.084 ;
    END
  END xs_q0[188]
  PIN xs_q0[189]
    DIRECTION INPUT ;
    USE SIGNAL ;
    PORT
      LAYER M5 ;
        RECT  260.736 0 260.76 0.084 ;
    END
  END xs_q0[189]
  PIN xs_q0[18]
    DIRECTION INPUT ;
    USE SIGNAL ;
    PORT
      LAYER M5 ;
        RECT  244.32 0 244.344 0.084 ;
    END
  END xs_q0[18]
  PIN xs_q0[190]
    DIRECTION INPUT ;
    USE SIGNAL ;
    PORT
      LAYER M5 ;
        RECT  260.832 0 260.856 0.084 ;
    END
  END xs_q0[190]
  PIN xs_q0[191]
    DIRECTION INPUT ;
    USE SIGNAL ;
    PORT
      LAYER M5 ;
        RECT  260.928 0 260.952 0.084 ;
    END
  END xs_q0[191]
  PIN xs_q0[192]
    DIRECTION INPUT ;
    USE SIGNAL ;
    PORT
      LAYER M5 ;
        RECT  261.024 0 261.048 0.084 ;
    END
  END xs_q0[192]
  PIN xs_q0[193]
    DIRECTION INPUT ;
    USE SIGNAL ;
    PORT
      LAYER M5 ;
        RECT  261.12 0 261.144 0.084 ;
    END
  END xs_q0[193]
  PIN xs_q0[194]
    DIRECTION INPUT ;
    USE SIGNAL ;
    PORT
      LAYER M5 ;
        RECT  261.216 0 261.24 0.084 ;
    END
  END xs_q0[194]
  PIN xs_q0[195]
    DIRECTION INPUT ;
    USE SIGNAL ;
    PORT
      LAYER M5 ;
        RECT  261.312 0 261.336 0.084 ;
    END
  END xs_q0[195]
  PIN xs_q0[196]
    DIRECTION INPUT ;
    USE SIGNAL ;
    PORT
      LAYER M5 ;
        RECT  261.408 0 261.432 0.084 ;
    END
  END xs_q0[196]
  PIN xs_q0[197]
    DIRECTION INPUT ;
    USE SIGNAL ;
    PORT
      LAYER M5 ;
        RECT  261.504 0 261.528 0.084 ;
    END
  END xs_q0[197]
  PIN xs_q0[198]
    DIRECTION INPUT ;
    USE SIGNAL ;
    PORT
      LAYER M5 ;
        RECT  261.6 0 261.624 0.084 ;
    END
  END xs_q0[198]
  PIN xs_q0[199]
    DIRECTION INPUT ;
    USE SIGNAL ;
    PORT
      LAYER M5 ;
        RECT  261.696 0 261.72 0.084 ;
    END
  END xs_q0[199]
  PIN xs_q0[19]
    DIRECTION INPUT ;
    USE SIGNAL ;
    PORT
      LAYER M5 ;
        RECT  244.416 0 244.44 0.084 ;
    END
  END xs_q0[19]
  PIN xs_q0[1]
    DIRECTION INPUT ;
    USE SIGNAL ;
    PORT
      LAYER M5 ;
        RECT  242.688 0 242.712 0.084 ;
    END
  END xs_q0[1]
  PIN xs_q0[200]
    DIRECTION INPUT ;
    USE SIGNAL ;
    PORT
      LAYER M5 ;
        RECT  261.792 0 261.816 0.084 ;
    END
  END xs_q0[200]
  PIN xs_q0[201]
    DIRECTION INPUT ;
    USE SIGNAL ;
    PORT
      LAYER M5 ;
        RECT  261.888 0 261.912 0.084 ;
    END
  END xs_q0[201]
  PIN xs_q0[202]
    DIRECTION INPUT ;
    USE SIGNAL ;
    PORT
      LAYER M5 ;
        RECT  261.984 0 262.008 0.084 ;
    END
  END xs_q0[202]
  PIN xs_q0[203]
    DIRECTION INPUT ;
    USE SIGNAL ;
    PORT
      LAYER M5 ;
        RECT  262.08 0 262.104 0.084 ;
    END
  END xs_q0[203]
  PIN xs_q0[204]
    DIRECTION INPUT ;
    USE SIGNAL ;
    PORT
      LAYER M5 ;
        RECT  262.176 0 262.2 0.084 ;
    END
  END xs_q0[204]
  PIN xs_q0[205]
    DIRECTION INPUT ;
    USE SIGNAL ;
    PORT
      LAYER M5 ;
        RECT  262.272 0 262.296 0.084 ;
    END
  END xs_q0[205]
  PIN xs_q0[206]
    DIRECTION INPUT ;
    USE SIGNAL ;
    PORT
      LAYER M5 ;
        RECT  262.368 0 262.392 0.084 ;
    END
  END xs_q0[206]
  PIN xs_q0[207]
    DIRECTION INPUT ;
    USE SIGNAL ;
    PORT
      LAYER M5 ;
        RECT  262.464 0 262.488 0.084 ;
    END
  END xs_q0[207]
  PIN xs_q0[208]
    DIRECTION INPUT ;
    USE SIGNAL ;
    PORT
      LAYER M5 ;
        RECT  262.56 0 262.584 0.084 ;
    END
  END xs_q0[208]
  PIN xs_q0[209]
    DIRECTION INPUT ;
    USE SIGNAL ;
    PORT
      LAYER M5 ;
        RECT  262.656 0 262.68 0.084 ;
    END
  END xs_q0[209]
  PIN xs_q0[20]
    DIRECTION INPUT ;
    USE SIGNAL ;
    PORT
      LAYER M5 ;
        RECT  244.512 0 244.536 0.084 ;
    END
  END xs_q0[20]
  PIN xs_q0[210]
    DIRECTION INPUT ;
    USE SIGNAL ;
    PORT
      LAYER M5 ;
        RECT  262.752 0 262.776 0.084 ;
    END
  END xs_q0[210]
  PIN xs_q0[211]
    DIRECTION INPUT ;
    USE SIGNAL ;
    PORT
      LAYER M5 ;
        RECT  262.848 0 262.872 0.084 ;
    END
  END xs_q0[211]
  PIN xs_q0[212]
    DIRECTION INPUT ;
    USE SIGNAL ;
    PORT
      LAYER M5 ;
        RECT  262.944 0 262.968 0.084 ;
    END
  END xs_q0[212]
  PIN xs_q0[213]
    DIRECTION INPUT ;
    USE SIGNAL ;
    PORT
      LAYER M5 ;
        RECT  263.04 0 263.064 0.084 ;
    END
  END xs_q0[213]
  PIN xs_q0[214]
    DIRECTION INPUT ;
    USE SIGNAL ;
    PORT
      LAYER M5 ;
        RECT  263.136 0 263.16 0.084 ;
    END
  END xs_q0[214]
  PIN xs_q0[215]
    DIRECTION INPUT ;
    USE SIGNAL ;
    PORT
      LAYER M5 ;
        RECT  263.232 0 263.256 0.084 ;
    END
  END xs_q0[215]
  PIN xs_q0[216]
    DIRECTION INPUT ;
    USE SIGNAL ;
    PORT
      LAYER M5 ;
        RECT  263.328 0 263.352 0.084 ;
    END
  END xs_q0[216]
  PIN xs_q0[217]
    DIRECTION INPUT ;
    USE SIGNAL ;
    PORT
      LAYER M5 ;
        RECT  263.424 0 263.448 0.084 ;
    END
  END xs_q0[217]
  PIN xs_q0[218]
    DIRECTION INPUT ;
    USE SIGNAL ;
    PORT
      LAYER M5 ;
        RECT  263.52 0 263.544 0.084 ;
    END
  END xs_q0[218]
  PIN xs_q0[219]
    DIRECTION INPUT ;
    USE SIGNAL ;
    PORT
      LAYER M5 ;
        RECT  263.616 0 263.64 0.084 ;
    END
  END xs_q0[219]
  PIN xs_q0[21]
    DIRECTION INPUT ;
    USE SIGNAL ;
    PORT
      LAYER M5 ;
        RECT  244.608 0 244.632 0.084 ;
    END
  END xs_q0[21]
  PIN xs_q0[220]
    DIRECTION INPUT ;
    USE SIGNAL ;
    PORT
      LAYER M5 ;
        RECT  263.712 0 263.736 0.084 ;
    END
  END xs_q0[220]
  PIN xs_q0[221]
    DIRECTION INPUT ;
    USE SIGNAL ;
    PORT
      LAYER M5 ;
        RECT  263.808 0 263.832 0.084 ;
    END
  END xs_q0[221]
  PIN xs_q0[222]
    DIRECTION INPUT ;
    USE SIGNAL ;
    PORT
      LAYER M5 ;
        RECT  263.904 0 263.928 0.084 ;
    END
  END xs_q0[222]
  PIN xs_q0[223]
    DIRECTION INPUT ;
    USE SIGNAL ;
    PORT
      LAYER M5 ;
        RECT  264 0 264.024 0.084 ;
    END
  END xs_q0[223]
  PIN xs_q0[224]
    DIRECTION INPUT ;
    USE SIGNAL ;
    PORT
      LAYER M5 ;
        RECT  264.096 0 264.12 0.084 ;
    END
  END xs_q0[224]
  PIN xs_q0[225]
    DIRECTION INPUT ;
    USE SIGNAL ;
    PORT
      LAYER M5 ;
        RECT  264.192 0 264.216 0.084 ;
    END
  END xs_q0[225]
  PIN xs_q0[226]
    DIRECTION INPUT ;
    USE SIGNAL ;
    PORT
      LAYER M5 ;
        RECT  264.288 0 264.312 0.084 ;
    END
  END xs_q0[226]
  PIN xs_q0[227]
    DIRECTION INPUT ;
    USE SIGNAL ;
    PORT
      LAYER M5 ;
        RECT  264.384 0 264.408 0.084 ;
    END
  END xs_q0[227]
  PIN xs_q0[228]
    DIRECTION INPUT ;
    USE SIGNAL ;
    PORT
      LAYER M5 ;
        RECT  264.48 0 264.504 0.084 ;
    END
  END xs_q0[228]
  PIN xs_q0[229]
    DIRECTION INPUT ;
    USE SIGNAL ;
    PORT
      LAYER M5 ;
        RECT  264.576 0 264.6 0.084 ;
    END
  END xs_q0[229]
  PIN xs_q0[22]
    DIRECTION INPUT ;
    USE SIGNAL ;
    PORT
      LAYER M5 ;
        RECT  244.704 0 244.728 0.084 ;
    END
  END xs_q0[22]
  PIN xs_q0[230]
    DIRECTION INPUT ;
    USE SIGNAL ;
    PORT
      LAYER M5 ;
        RECT  264.672 0 264.696 0.084 ;
    END
  END xs_q0[230]
  PIN xs_q0[231]
    DIRECTION INPUT ;
    USE SIGNAL ;
    PORT
      LAYER M5 ;
        RECT  264.768 0 264.792 0.084 ;
    END
  END xs_q0[231]
  PIN xs_q0[232]
    DIRECTION INPUT ;
    USE SIGNAL ;
    PORT
      LAYER M5 ;
        RECT  264.864 0 264.888 0.084 ;
    END
  END xs_q0[232]
  PIN xs_q0[233]
    DIRECTION INPUT ;
    USE SIGNAL ;
    PORT
      LAYER M5 ;
        RECT  264.96 0 264.984 0.084 ;
    END
  END xs_q0[233]
  PIN xs_q0[234]
    DIRECTION INPUT ;
    USE SIGNAL ;
    PORT
      LAYER M5 ;
        RECT  265.056 0 265.08 0.084 ;
    END
  END xs_q0[234]
  PIN xs_q0[235]
    DIRECTION INPUT ;
    USE SIGNAL ;
    PORT
      LAYER M5 ;
        RECT  265.152 0 265.176 0.084 ;
    END
  END xs_q0[235]
  PIN xs_q0[236]
    DIRECTION INPUT ;
    USE SIGNAL ;
    PORT
      LAYER M5 ;
        RECT  265.248 0 265.272 0.084 ;
    END
  END xs_q0[236]
  PIN xs_q0[237]
    DIRECTION INPUT ;
    USE SIGNAL ;
    PORT
      LAYER M5 ;
        RECT  265.344 0 265.368 0.084 ;
    END
  END xs_q0[237]
  PIN xs_q0[238]
    DIRECTION INPUT ;
    USE SIGNAL ;
    PORT
      LAYER M5 ;
        RECT  265.44 0 265.464 0.084 ;
    END
  END xs_q0[238]
  PIN xs_q0[239]
    DIRECTION INPUT ;
    USE SIGNAL ;
    PORT
      LAYER M5 ;
        RECT  265.536 0 265.56 0.084 ;
    END
  END xs_q0[239]
  PIN xs_q0[23]
    DIRECTION INPUT ;
    USE SIGNAL ;
    PORT
      LAYER M5 ;
        RECT  244.8 0 244.824 0.084 ;
    END
  END xs_q0[23]
  PIN xs_q0[240]
    DIRECTION INPUT ;
    USE SIGNAL ;
    PORT
      LAYER M5 ;
        RECT  265.632 0 265.656 0.084 ;
    END
  END xs_q0[240]
  PIN xs_q0[241]
    DIRECTION INPUT ;
    USE SIGNAL ;
    PORT
      LAYER M5 ;
        RECT  265.728 0 265.752 0.084 ;
    END
  END xs_q0[241]
  PIN xs_q0[242]
    DIRECTION INPUT ;
    USE SIGNAL ;
    PORT
      LAYER M5 ;
        RECT  265.824 0 265.848 0.084 ;
    END
  END xs_q0[242]
  PIN xs_q0[243]
    DIRECTION INPUT ;
    USE SIGNAL ;
    PORT
      LAYER M5 ;
        RECT  265.92 0 265.944 0.084 ;
    END
  END xs_q0[243]
  PIN xs_q0[244]
    DIRECTION INPUT ;
    USE SIGNAL ;
    PORT
      LAYER M5 ;
        RECT  266.016 0 266.04 0.084 ;
    END
  END xs_q0[244]
  PIN xs_q0[245]
    DIRECTION INPUT ;
    USE SIGNAL ;
    PORT
      LAYER M5 ;
        RECT  266.112 0 266.136 0.084 ;
    END
  END xs_q0[245]
  PIN xs_q0[246]
    DIRECTION INPUT ;
    USE SIGNAL ;
    PORT
      LAYER M5 ;
        RECT  266.208 0 266.232 0.084 ;
    END
  END xs_q0[246]
  PIN xs_q0[247]
    DIRECTION INPUT ;
    USE SIGNAL ;
    PORT
      LAYER M5 ;
        RECT  266.304 0 266.328 0.084 ;
    END
  END xs_q0[247]
  PIN xs_q0[248]
    DIRECTION INPUT ;
    USE SIGNAL ;
    PORT
      LAYER M5 ;
        RECT  266.4 0 266.424 0.084 ;
    END
  END xs_q0[248]
  PIN xs_q0[249]
    DIRECTION INPUT ;
    USE SIGNAL ;
    PORT
      LAYER M5 ;
        RECT  266.496 0 266.52 0.084 ;
    END
  END xs_q0[249]
  PIN xs_q0[24]
    DIRECTION INPUT ;
    USE SIGNAL ;
    PORT
      LAYER M5 ;
        RECT  244.896 0 244.92 0.084 ;
    END
  END xs_q0[24]
  PIN xs_q0[250]
    DIRECTION INPUT ;
    USE SIGNAL ;
    PORT
      LAYER M5 ;
        RECT  266.592 0 266.616 0.084 ;
    END
  END xs_q0[250]
  PIN xs_q0[251]
    DIRECTION INPUT ;
    USE SIGNAL ;
    PORT
      LAYER M5 ;
        RECT  266.688 0 266.712 0.084 ;
    END
  END xs_q0[251]
  PIN xs_q0[252]
    DIRECTION INPUT ;
    USE SIGNAL ;
    PORT
      LAYER M5 ;
        RECT  266.784 0 266.808 0.084 ;
    END
  END xs_q0[252]
  PIN xs_q0[253]
    DIRECTION INPUT ;
    USE SIGNAL ;
    PORT
      LAYER M5 ;
        RECT  266.88 0 266.904 0.084 ;
    END
  END xs_q0[253]
  PIN xs_q0[254]
    DIRECTION INPUT ;
    USE SIGNAL ;
    PORT
      LAYER M5 ;
        RECT  266.976 0 267 0.084 ;
    END
  END xs_q0[254]
  PIN xs_q0[255]
    DIRECTION INPUT ;
    USE SIGNAL ;
    PORT
      LAYER M5 ;
        RECT  267.072 0 267.096 0.084 ;
    END
  END xs_q0[255]
  PIN xs_q0[25]
    DIRECTION INPUT ;
    USE SIGNAL ;
    PORT
      LAYER M5 ;
        RECT  244.992 0 245.016 0.084 ;
    END
  END xs_q0[25]
  PIN xs_q0[26]
    DIRECTION INPUT ;
    USE SIGNAL ;
    PORT
      LAYER M5 ;
        RECT  245.088 0 245.112 0.084 ;
    END
  END xs_q0[26]
  PIN xs_q0[27]
    DIRECTION INPUT ;
    USE SIGNAL ;
    PORT
      LAYER M5 ;
        RECT  245.184 0 245.208 0.084 ;
    END
  END xs_q0[27]
  PIN xs_q0[28]
    DIRECTION INPUT ;
    USE SIGNAL ;
    PORT
      LAYER M5 ;
        RECT  245.28 0 245.304 0.084 ;
    END
  END xs_q0[28]
  PIN xs_q0[29]
    DIRECTION INPUT ;
    USE SIGNAL ;
    PORT
      LAYER M5 ;
        RECT  245.376 0 245.4 0.084 ;
    END
  END xs_q0[29]
  PIN xs_q0[2]
    DIRECTION INPUT ;
    USE SIGNAL ;
    PORT
      LAYER M5 ;
        RECT  242.784 0 242.808 0.084 ;
    END
  END xs_q0[2]
  PIN xs_q0[30]
    DIRECTION INPUT ;
    USE SIGNAL ;
    PORT
      LAYER M5 ;
        RECT  245.472 0 245.496 0.084 ;
    END
  END xs_q0[30]
  PIN xs_q0[31]
    DIRECTION INPUT ;
    USE SIGNAL ;
    PORT
      LAYER M5 ;
        RECT  245.568 0 245.592 0.084 ;
    END
  END xs_q0[31]
  PIN xs_q0[32]
    DIRECTION INPUT ;
    USE SIGNAL ;
    PORT
      LAYER M5 ;
        RECT  245.664 0 245.688 0.084 ;
    END
  END xs_q0[32]
  PIN xs_q0[33]
    DIRECTION INPUT ;
    USE SIGNAL ;
    PORT
      LAYER M5 ;
        RECT  245.76 0 245.784 0.084 ;
    END
  END xs_q0[33]
  PIN xs_q0[34]
    DIRECTION INPUT ;
    USE SIGNAL ;
    PORT
      LAYER M5 ;
        RECT  245.856 0 245.88 0.084 ;
    END
  END xs_q0[34]
  PIN xs_q0[35]
    DIRECTION INPUT ;
    USE SIGNAL ;
    PORT
      LAYER M5 ;
        RECT  245.952 0 245.976 0.084 ;
    END
  END xs_q0[35]
  PIN xs_q0[36]
    DIRECTION INPUT ;
    USE SIGNAL ;
    PORT
      LAYER M5 ;
        RECT  246.048 0 246.072 0.084 ;
    END
  END xs_q0[36]
  PIN xs_q0[37]
    DIRECTION INPUT ;
    USE SIGNAL ;
    PORT
      LAYER M5 ;
        RECT  246.144 0 246.168 0.084 ;
    END
  END xs_q0[37]
  PIN xs_q0[38]
    DIRECTION INPUT ;
    USE SIGNAL ;
    PORT
      LAYER M5 ;
        RECT  246.24 0 246.264 0.084 ;
    END
  END xs_q0[38]
  PIN xs_q0[39]
    DIRECTION INPUT ;
    USE SIGNAL ;
    PORT
      LAYER M5 ;
        RECT  246.336 0 246.36 0.084 ;
    END
  END xs_q0[39]
  PIN xs_q0[3]
    DIRECTION INPUT ;
    USE SIGNAL ;
    PORT
      LAYER M5 ;
        RECT  242.88 0 242.904 0.084 ;
    END
  END xs_q0[3]
  PIN xs_q0[40]
    DIRECTION INPUT ;
    USE SIGNAL ;
    PORT
      LAYER M5 ;
        RECT  246.432 0 246.456 0.084 ;
    END
  END xs_q0[40]
  PIN xs_q0[41]
    DIRECTION INPUT ;
    USE SIGNAL ;
    PORT
      LAYER M5 ;
        RECT  246.528 0 246.552 0.084 ;
    END
  END xs_q0[41]
  PIN xs_q0[42]
    DIRECTION INPUT ;
    USE SIGNAL ;
    PORT
      LAYER M5 ;
        RECT  246.624 0 246.648 0.084 ;
    END
  END xs_q0[42]
  PIN xs_q0[43]
    DIRECTION INPUT ;
    USE SIGNAL ;
    PORT
      LAYER M5 ;
        RECT  246.72 0 246.744 0.084 ;
    END
  END xs_q0[43]
  PIN xs_q0[44]
    DIRECTION INPUT ;
    USE SIGNAL ;
    PORT
      LAYER M5 ;
        RECT  246.816 0 246.84 0.084 ;
    END
  END xs_q0[44]
  PIN xs_q0[45]
    DIRECTION INPUT ;
    USE SIGNAL ;
    PORT
      LAYER M5 ;
        RECT  246.912 0 246.936 0.084 ;
    END
  END xs_q0[45]
  PIN xs_q0[46]
    DIRECTION INPUT ;
    USE SIGNAL ;
    PORT
      LAYER M5 ;
        RECT  247.008 0 247.032 0.084 ;
    END
  END xs_q0[46]
  PIN xs_q0[47]
    DIRECTION INPUT ;
    USE SIGNAL ;
    PORT
      LAYER M5 ;
        RECT  247.104 0 247.128 0.084 ;
    END
  END xs_q0[47]
  PIN xs_q0[48]
    DIRECTION INPUT ;
    USE SIGNAL ;
    PORT
      LAYER M5 ;
        RECT  247.2 0 247.224 0.084 ;
    END
  END xs_q0[48]
  PIN xs_q0[49]
    DIRECTION INPUT ;
    USE SIGNAL ;
    PORT
      LAYER M5 ;
        RECT  247.296 0 247.32 0.084 ;
    END
  END xs_q0[49]
  PIN xs_q0[4]
    DIRECTION INPUT ;
    USE SIGNAL ;
    PORT
      LAYER M5 ;
        RECT  242.976 0 243 0.084 ;
    END
  END xs_q0[4]
  PIN xs_q0[50]
    DIRECTION INPUT ;
    USE SIGNAL ;
    PORT
      LAYER M5 ;
        RECT  247.392 0 247.416 0.084 ;
    END
  END xs_q0[50]
  PIN xs_q0[51]
    DIRECTION INPUT ;
    USE SIGNAL ;
    PORT
      LAYER M5 ;
        RECT  247.488 0 247.512 0.084 ;
    END
  END xs_q0[51]
  PIN xs_q0[52]
    DIRECTION INPUT ;
    USE SIGNAL ;
    PORT
      LAYER M5 ;
        RECT  247.584 0 247.608 0.084 ;
    END
  END xs_q0[52]
  PIN xs_q0[53]
    DIRECTION INPUT ;
    USE SIGNAL ;
    PORT
      LAYER M5 ;
        RECT  247.68 0 247.704 0.084 ;
    END
  END xs_q0[53]
  PIN xs_q0[54]
    DIRECTION INPUT ;
    USE SIGNAL ;
    PORT
      LAYER M5 ;
        RECT  247.776 0 247.8 0.084 ;
    END
  END xs_q0[54]
  PIN xs_q0[55]
    DIRECTION INPUT ;
    USE SIGNAL ;
    PORT
      LAYER M5 ;
        RECT  247.872 0 247.896 0.084 ;
    END
  END xs_q0[55]
  PIN xs_q0[56]
    DIRECTION INPUT ;
    USE SIGNAL ;
    PORT
      LAYER M5 ;
        RECT  247.968 0 247.992 0.084 ;
    END
  END xs_q0[56]
  PIN xs_q0[57]
    DIRECTION INPUT ;
    USE SIGNAL ;
    PORT
      LAYER M5 ;
        RECT  248.064 0 248.088 0.084 ;
    END
  END xs_q0[57]
  PIN xs_q0[58]
    DIRECTION INPUT ;
    USE SIGNAL ;
    PORT
      LAYER M5 ;
        RECT  248.16 0 248.184 0.084 ;
    END
  END xs_q0[58]
  PIN xs_q0[59]
    DIRECTION INPUT ;
    USE SIGNAL ;
    PORT
      LAYER M5 ;
        RECT  248.256 0 248.28 0.084 ;
    END
  END xs_q0[59]
  PIN xs_q0[5]
    DIRECTION INPUT ;
    USE SIGNAL ;
    PORT
      LAYER M5 ;
        RECT  243.072 0 243.096 0.084 ;
    END
  END xs_q0[5]
  PIN xs_q0[60]
    DIRECTION INPUT ;
    USE SIGNAL ;
    PORT
      LAYER M5 ;
        RECT  248.352 0 248.376 0.084 ;
    END
  END xs_q0[60]
  PIN xs_q0[61]
    DIRECTION INPUT ;
    USE SIGNAL ;
    PORT
      LAYER M5 ;
        RECT  248.448 0 248.472 0.084 ;
    END
  END xs_q0[61]
  PIN xs_q0[62]
    DIRECTION INPUT ;
    USE SIGNAL ;
    PORT
      LAYER M5 ;
        RECT  248.544 0 248.568 0.084 ;
    END
  END xs_q0[62]
  PIN xs_q0[63]
    DIRECTION INPUT ;
    USE SIGNAL ;
    PORT
      LAYER M5 ;
        RECT  248.64 0 248.664 0.084 ;
    END
  END xs_q0[63]
  PIN xs_q0[64]
    DIRECTION INPUT ;
    USE SIGNAL ;
    PORT
      LAYER M5 ;
        RECT  248.736 0 248.76 0.084 ;
    END
  END xs_q0[64]
  PIN xs_q0[65]
    DIRECTION INPUT ;
    USE SIGNAL ;
    PORT
      LAYER M5 ;
        RECT  248.832 0 248.856 0.084 ;
    END
  END xs_q0[65]
  PIN xs_q0[66]
    DIRECTION INPUT ;
    USE SIGNAL ;
    PORT
      LAYER M5 ;
        RECT  248.928 0 248.952 0.084 ;
    END
  END xs_q0[66]
  PIN xs_q0[67]
    DIRECTION INPUT ;
    USE SIGNAL ;
    PORT
      LAYER M5 ;
        RECT  249.024 0 249.048 0.084 ;
    END
  END xs_q0[67]
  PIN xs_q0[68]
    DIRECTION INPUT ;
    USE SIGNAL ;
    PORT
      LAYER M5 ;
        RECT  249.12 0 249.144 0.084 ;
    END
  END xs_q0[68]
  PIN xs_q0[69]
    DIRECTION INPUT ;
    USE SIGNAL ;
    PORT
      LAYER M5 ;
        RECT  249.216 0 249.24 0.084 ;
    END
  END xs_q0[69]
  PIN xs_q0[6]
    DIRECTION INPUT ;
    USE SIGNAL ;
    PORT
      LAYER M5 ;
        RECT  243.168 0 243.192 0.084 ;
    END
  END xs_q0[6]
  PIN xs_q0[70]
    DIRECTION INPUT ;
    USE SIGNAL ;
    PORT
      LAYER M5 ;
        RECT  249.312 0 249.336 0.084 ;
    END
  END xs_q0[70]
  PIN xs_q0[71]
    DIRECTION INPUT ;
    USE SIGNAL ;
    PORT
      LAYER M5 ;
        RECT  249.408 0 249.432 0.084 ;
    END
  END xs_q0[71]
  PIN xs_q0[72]
    DIRECTION INPUT ;
    USE SIGNAL ;
    PORT
      LAYER M5 ;
        RECT  249.504 0 249.528 0.084 ;
    END
  END xs_q0[72]
  PIN xs_q0[73]
    DIRECTION INPUT ;
    USE SIGNAL ;
    PORT
      LAYER M5 ;
        RECT  249.6 0 249.624 0.084 ;
    END
  END xs_q0[73]
  PIN xs_q0[74]
    DIRECTION INPUT ;
    USE SIGNAL ;
    PORT
      LAYER M5 ;
        RECT  249.696 0 249.72 0.084 ;
    END
  END xs_q0[74]
  PIN xs_q0[75]
    DIRECTION INPUT ;
    USE SIGNAL ;
    PORT
      LAYER M5 ;
        RECT  249.792 0 249.816 0.084 ;
    END
  END xs_q0[75]
  PIN xs_q0[76]
    DIRECTION INPUT ;
    USE SIGNAL ;
    PORT
      LAYER M5 ;
        RECT  249.888 0 249.912 0.084 ;
    END
  END xs_q0[76]
  PIN xs_q0[77]
    DIRECTION INPUT ;
    USE SIGNAL ;
    PORT
      LAYER M5 ;
        RECT  249.984 0 250.008 0.084 ;
    END
  END xs_q0[77]
  PIN xs_q0[78]
    DIRECTION INPUT ;
    USE SIGNAL ;
    PORT
      LAYER M5 ;
        RECT  250.08 0 250.104 0.084 ;
    END
  END xs_q0[78]
  PIN xs_q0[79]
    DIRECTION INPUT ;
    USE SIGNAL ;
    PORT
      LAYER M5 ;
        RECT  250.176 0 250.2 0.084 ;
    END
  END xs_q0[79]
  PIN xs_q0[7]
    DIRECTION INPUT ;
    USE SIGNAL ;
    PORT
      LAYER M5 ;
        RECT  243.264 0 243.288 0.084 ;
    END
  END xs_q0[7]
  PIN xs_q0[80]
    DIRECTION INPUT ;
    USE SIGNAL ;
    PORT
      LAYER M5 ;
        RECT  250.272 0 250.296 0.084 ;
    END
  END xs_q0[80]
  PIN xs_q0[81]
    DIRECTION INPUT ;
    USE SIGNAL ;
    PORT
      LAYER M5 ;
        RECT  250.368 0 250.392 0.084 ;
    END
  END xs_q0[81]
  PIN xs_q0[82]
    DIRECTION INPUT ;
    USE SIGNAL ;
    PORT
      LAYER M5 ;
        RECT  250.464 0 250.488 0.084 ;
    END
  END xs_q0[82]
  PIN xs_q0[83]
    DIRECTION INPUT ;
    USE SIGNAL ;
    PORT
      LAYER M5 ;
        RECT  250.56 0 250.584 0.084 ;
    END
  END xs_q0[83]
  PIN xs_q0[84]
    DIRECTION INPUT ;
    USE SIGNAL ;
    PORT
      LAYER M5 ;
        RECT  250.656 0 250.68 0.084 ;
    END
  END xs_q0[84]
  PIN xs_q0[85]
    DIRECTION INPUT ;
    USE SIGNAL ;
    PORT
      LAYER M5 ;
        RECT  250.752 0 250.776 0.084 ;
    END
  END xs_q0[85]
  PIN xs_q0[86]
    DIRECTION INPUT ;
    USE SIGNAL ;
    PORT
      LAYER M5 ;
        RECT  250.848 0 250.872 0.084 ;
    END
  END xs_q0[86]
  PIN xs_q0[87]
    DIRECTION INPUT ;
    USE SIGNAL ;
    PORT
      LAYER M5 ;
        RECT  250.944 0 250.968 0.084 ;
    END
  END xs_q0[87]
  PIN xs_q0[88]
    DIRECTION INPUT ;
    USE SIGNAL ;
    PORT
      LAYER M5 ;
        RECT  251.04 0 251.064 0.084 ;
    END
  END xs_q0[88]
  PIN xs_q0[89]
    DIRECTION INPUT ;
    USE SIGNAL ;
    PORT
      LAYER M5 ;
        RECT  251.136 0 251.16 0.084 ;
    END
  END xs_q0[89]
  PIN xs_q0[8]
    DIRECTION INPUT ;
    USE SIGNAL ;
    PORT
      LAYER M5 ;
        RECT  243.36 0 243.384 0.084 ;
    END
  END xs_q0[8]
  PIN xs_q0[90]
    DIRECTION INPUT ;
    USE SIGNAL ;
    PORT
      LAYER M5 ;
        RECT  251.232 0 251.256 0.084 ;
    END
  END xs_q0[90]
  PIN xs_q0[91]
    DIRECTION INPUT ;
    USE SIGNAL ;
    PORT
      LAYER M5 ;
        RECT  251.328 0 251.352 0.084 ;
    END
  END xs_q0[91]
  PIN xs_q0[92]
    DIRECTION INPUT ;
    USE SIGNAL ;
    PORT
      LAYER M5 ;
        RECT  251.424 0 251.448 0.084 ;
    END
  END xs_q0[92]
  PIN xs_q0[93]
    DIRECTION INPUT ;
    USE SIGNAL ;
    PORT
      LAYER M5 ;
        RECT  251.52 0 251.544 0.084 ;
    END
  END xs_q0[93]
  PIN xs_q0[94]
    DIRECTION INPUT ;
    USE SIGNAL ;
    PORT
      LAYER M5 ;
        RECT  251.616 0 251.64 0.084 ;
    END
  END xs_q0[94]
  PIN xs_q0[95]
    DIRECTION INPUT ;
    USE SIGNAL ;
    PORT
      LAYER M5 ;
        RECT  251.712 0 251.736 0.084 ;
    END
  END xs_q0[95]
  PIN xs_q0[96]
    DIRECTION INPUT ;
    USE SIGNAL ;
    PORT
      LAYER M5 ;
        RECT  251.808 0 251.832 0.084 ;
    END
  END xs_q0[96]
  PIN xs_q0[97]
    DIRECTION INPUT ;
    USE SIGNAL ;
    PORT
      LAYER M5 ;
        RECT  251.904 0 251.928 0.084 ;
    END
  END xs_q0[97]
  PIN xs_q0[98]
    DIRECTION INPUT ;
    USE SIGNAL ;
    PORT
      LAYER M5 ;
        RECT  252 0 252.024 0.084 ;
    END
  END xs_q0[98]
  PIN xs_q0[99]
    DIRECTION INPUT ;
    USE SIGNAL ;
    PORT
      LAYER M5 ;
        RECT  252.096 0 252.12 0.084 ;
    END
  END xs_q0[99]
  PIN xs_q0[9]
    DIRECTION INPUT ;
    USE SIGNAL ;
    PORT
      LAYER M5 ;
        RECT  243.456 0 243.48 0.084 ;
    END
  END xs_q0[9]
  PIN xs_q1[0]
    DIRECTION INPUT ;
    USE SIGNAL ;
    PORT
      LAYER M5 ;
        RECT  267.168 0 267.192 0.084 ;
    END
  END xs_q1[0]
  PIN xs_q1[100]
    DIRECTION INPUT ;
    USE SIGNAL ;
    PORT
      LAYER M5 ;
        RECT  276.768 0 276.792 0.084 ;
    END
  END xs_q1[100]
  PIN xs_q1[101]
    DIRECTION INPUT ;
    USE SIGNAL ;
    PORT
      LAYER M5 ;
        RECT  276.864 0 276.888 0.084 ;
    END
  END xs_q1[101]
  PIN xs_q1[102]
    DIRECTION INPUT ;
    USE SIGNAL ;
    PORT
      LAYER M5 ;
        RECT  276.96 0 276.984 0.084 ;
    END
  END xs_q1[102]
  PIN xs_q1[103]
    DIRECTION INPUT ;
    USE SIGNAL ;
    PORT
      LAYER M5 ;
        RECT  277.056 0 277.08 0.084 ;
    END
  END xs_q1[103]
  PIN xs_q1[104]
    DIRECTION INPUT ;
    USE SIGNAL ;
    PORT
      LAYER M5 ;
        RECT  277.152 0 277.176 0.084 ;
    END
  END xs_q1[104]
  PIN xs_q1[105]
    DIRECTION INPUT ;
    USE SIGNAL ;
    PORT
      LAYER M5 ;
        RECT  277.248 0 277.272 0.084 ;
    END
  END xs_q1[105]
  PIN xs_q1[106]
    DIRECTION INPUT ;
    USE SIGNAL ;
    PORT
      LAYER M5 ;
        RECT  277.344 0 277.368 0.084 ;
    END
  END xs_q1[106]
  PIN xs_q1[107]
    DIRECTION INPUT ;
    USE SIGNAL ;
    PORT
      LAYER M5 ;
        RECT  277.44 0 277.464 0.084 ;
    END
  END xs_q1[107]
  PIN xs_q1[108]
    DIRECTION INPUT ;
    USE SIGNAL ;
    PORT
      LAYER M5 ;
        RECT  277.536 0 277.56 0.084 ;
    END
  END xs_q1[108]
  PIN xs_q1[109]
    DIRECTION INPUT ;
    USE SIGNAL ;
    PORT
      LAYER M5 ;
        RECT  277.632 0 277.656 0.084 ;
    END
  END xs_q1[109]
  PIN xs_q1[10]
    DIRECTION INPUT ;
    USE SIGNAL ;
    PORT
      LAYER M5 ;
        RECT  268.128 0 268.152 0.084 ;
    END
  END xs_q1[10]
  PIN xs_q1[110]
    DIRECTION INPUT ;
    USE SIGNAL ;
    PORT
      LAYER M5 ;
        RECT  277.728 0 277.752 0.084 ;
    END
  END xs_q1[110]
  PIN xs_q1[111]
    DIRECTION INPUT ;
    USE SIGNAL ;
    PORT
      LAYER M5 ;
        RECT  277.824 0 277.848 0.084 ;
    END
  END xs_q1[111]
  PIN xs_q1[112]
    DIRECTION INPUT ;
    USE SIGNAL ;
    PORT
      LAYER M5 ;
        RECT  277.92 0 277.944 0.084 ;
    END
  END xs_q1[112]
  PIN xs_q1[113]
    DIRECTION INPUT ;
    USE SIGNAL ;
    PORT
      LAYER M5 ;
        RECT  278.016 0 278.04 0.084 ;
    END
  END xs_q1[113]
  PIN xs_q1[114]
    DIRECTION INPUT ;
    USE SIGNAL ;
    PORT
      LAYER M5 ;
        RECT  278.112 0 278.136 0.084 ;
    END
  END xs_q1[114]
  PIN xs_q1[115]
    DIRECTION INPUT ;
    USE SIGNAL ;
    PORT
      LAYER M5 ;
        RECT  278.208 0 278.232 0.084 ;
    END
  END xs_q1[115]
  PIN xs_q1[116]
    DIRECTION INPUT ;
    USE SIGNAL ;
    PORT
      LAYER M5 ;
        RECT  278.304 0 278.328 0.084 ;
    END
  END xs_q1[116]
  PIN xs_q1[117]
    DIRECTION INPUT ;
    USE SIGNAL ;
    PORT
      LAYER M5 ;
        RECT  278.4 0 278.424 0.084 ;
    END
  END xs_q1[117]
  PIN xs_q1[118]
    DIRECTION INPUT ;
    USE SIGNAL ;
    PORT
      LAYER M5 ;
        RECT  278.496 0 278.52 0.084 ;
    END
  END xs_q1[118]
  PIN xs_q1[119]
    DIRECTION INPUT ;
    USE SIGNAL ;
    PORT
      LAYER M5 ;
        RECT  278.592 0 278.616 0.084 ;
    END
  END xs_q1[119]
  PIN xs_q1[11]
    DIRECTION INPUT ;
    USE SIGNAL ;
    PORT
      LAYER M5 ;
        RECT  268.224 0 268.248 0.084 ;
    END
  END xs_q1[11]
  PIN xs_q1[120]
    DIRECTION INPUT ;
    USE SIGNAL ;
    PORT
      LAYER M5 ;
        RECT  278.688 0 278.712 0.084 ;
    END
  END xs_q1[120]
  PIN xs_q1[121]
    DIRECTION INPUT ;
    USE SIGNAL ;
    PORT
      LAYER M5 ;
        RECT  278.784 0 278.808 0.084 ;
    END
  END xs_q1[121]
  PIN xs_q1[122]
    DIRECTION INPUT ;
    USE SIGNAL ;
    PORT
      LAYER M5 ;
        RECT  278.88 0 278.904 0.084 ;
    END
  END xs_q1[122]
  PIN xs_q1[123]
    DIRECTION INPUT ;
    USE SIGNAL ;
    PORT
      LAYER M5 ;
        RECT  278.976 0 279 0.084 ;
    END
  END xs_q1[123]
  PIN xs_q1[124]
    DIRECTION INPUT ;
    USE SIGNAL ;
    PORT
      LAYER M5 ;
        RECT  279.072 0 279.096 0.084 ;
    END
  END xs_q1[124]
  PIN xs_q1[125]
    DIRECTION INPUT ;
    USE SIGNAL ;
    PORT
      LAYER M5 ;
        RECT  279.168 0 279.192 0.084 ;
    END
  END xs_q1[125]
  PIN xs_q1[126]
    DIRECTION INPUT ;
    USE SIGNAL ;
    PORT
      LAYER M5 ;
        RECT  279.264 0 279.288 0.084 ;
    END
  END xs_q1[126]
  PIN xs_q1[127]
    DIRECTION INPUT ;
    USE SIGNAL ;
    PORT
      LAYER M5 ;
        RECT  279.36 0 279.384 0.084 ;
    END
  END xs_q1[127]
  PIN xs_q1[128]
    DIRECTION INPUT ;
    USE SIGNAL ;
    PORT
      LAYER M5 ;
        RECT  279.456 0 279.48 0.084 ;
    END
  END xs_q1[128]
  PIN xs_q1[129]
    DIRECTION INPUT ;
    USE SIGNAL ;
    PORT
      LAYER M5 ;
        RECT  279.552 0 279.576 0.084 ;
    END
  END xs_q1[129]
  PIN xs_q1[12]
    DIRECTION INPUT ;
    USE SIGNAL ;
    PORT
      LAYER M5 ;
        RECT  268.32 0 268.344 0.084 ;
    END
  END xs_q1[12]
  PIN xs_q1[130]
    DIRECTION INPUT ;
    USE SIGNAL ;
    PORT
      LAYER M5 ;
        RECT  279.648 0 279.672 0.084 ;
    END
  END xs_q1[130]
  PIN xs_q1[131]
    DIRECTION INPUT ;
    USE SIGNAL ;
    PORT
      LAYER M5 ;
        RECT  279.744 0 279.768 0.084 ;
    END
  END xs_q1[131]
  PIN xs_q1[132]
    DIRECTION INPUT ;
    USE SIGNAL ;
    PORT
      LAYER M5 ;
        RECT  279.84 0 279.864 0.084 ;
    END
  END xs_q1[132]
  PIN xs_q1[133]
    DIRECTION INPUT ;
    USE SIGNAL ;
    PORT
      LAYER M5 ;
        RECT  279.936 0 279.96 0.084 ;
    END
  END xs_q1[133]
  PIN xs_q1[134]
    DIRECTION INPUT ;
    USE SIGNAL ;
    PORT
      LAYER M5 ;
        RECT  280.032 0 280.056 0.084 ;
    END
  END xs_q1[134]
  PIN xs_q1[135]
    DIRECTION INPUT ;
    USE SIGNAL ;
    PORT
      LAYER M5 ;
        RECT  280.128 0 280.152 0.084 ;
    END
  END xs_q1[135]
  PIN xs_q1[136]
    DIRECTION INPUT ;
    USE SIGNAL ;
    PORT
      LAYER M5 ;
        RECT  280.224 0 280.248 0.084 ;
    END
  END xs_q1[136]
  PIN xs_q1[137]
    DIRECTION INPUT ;
    USE SIGNAL ;
    PORT
      LAYER M5 ;
        RECT  280.32 0 280.344 0.084 ;
    END
  END xs_q1[137]
  PIN xs_q1[138]
    DIRECTION INPUT ;
    USE SIGNAL ;
    PORT
      LAYER M5 ;
        RECT  280.416 0 280.44 0.084 ;
    END
  END xs_q1[138]
  PIN xs_q1[139]
    DIRECTION INPUT ;
    USE SIGNAL ;
    PORT
      LAYER M5 ;
        RECT  280.512 0 280.536 0.084 ;
    END
  END xs_q1[139]
  PIN xs_q1[13]
    DIRECTION INPUT ;
    USE SIGNAL ;
    PORT
      LAYER M5 ;
        RECT  268.416 0 268.44 0.084 ;
    END
  END xs_q1[13]
  PIN xs_q1[140]
    DIRECTION INPUT ;
    USE SIGNAL ;
    PORT
      LAYER M5 ;
        RECT  280.608 0 280.632 0.084 ;
    END
  END xs_q1[140]
  PIN xs_q1[141]
    DIRECTION INPUT ;
    USE SIGNAL ;
    PORT
      LAYER M5 ;
        RECT  280.704 0 280.728 0.084 ;
    END
  END xs_q1[141]
  PIN xs_q1[142]
    DIRECTION INPUT ;
    USE SIGNAL ;
    PORT
      LAYER M5 ;
        RECT  280.8 0 280.824 0.084 ;
    END
  END xs_q1[142]
  PIN xs_q1[143]
    DIRECTION INPUT ;
    USE SIGNAL ;
    PORT
      LAYER M5 ;
        RECT  280.896 0 280.92 0.084 ;
    END
  END xs_q1[143]
  PIN xs_q1[144]
    DIRECTION INPUT ;
    USE SIGNAL ;
    PORT
      LAYER M5 ;
        RECT  280.992 0 281.016 0.084 ;
    END
  END xs_q1[144]
  PIN xs_q1[145]
    DIRECTION INPUT ;
    USE SIGNAL ;
    PORT
      LAYER M5 ;
        RECT  281.088 0 281.112 0.084 ;
    END
  END xs_q1[145]
  PIN xs_q1[146]
    DIRECTION INPUT ;
    USE SIGNAL ;
    PORT
      LAYER M5 ;
        RECT  281.184 0 281.208 0.084 ;
    END
  END xs_q1[146]
  PIN xs_q1[147]
    DIRECTION INPUT ;
    USE SIGNAL ;
    PORT
      LAYER M5 ;
        RECT  281.28 0 281.304 0.084 ;
    END
  END xs_q1[147]
  PIN xs_q1[148]
    DIRECTION INPUT ;
    USE SIGNAL ;
    PORT
      LAYER M5 ;
        RECT  281.376 0 281.4 0.084 ;
    END
  END xs_q1[148]
  PIN xs_q1[149]
    DIRECTION INPUT ;
    USE SIGNAL ;
    PORT
      LAYER M5 ;
        RECT  281.472 0 281.496 0.084 ;
    END
  END xs_q1[149]
  PIN xs_q1[14]
    DIRECTION INPUT ;
    USE SIGNAL ;
    PORT
      LAYER M5 ;
        RECT  268.512 0 268.536 0.084 ;
    END
  END xs_q1[14]
  PIN xs_q1[150]
    DIRECTION INPUT ;
    USE SIGNAL ;
    PORT
      LAYER M5 ;
        RECT  281.568 0 281.592 0.084 ;
    END
  END xs_q1[150]
  PIN xs_q1[151]
    DIRECTION INPUT ;
    USE SIGNAL ;
    PORT
      LAYER M5 ;
        RECT  281.664 0 281.688 0.084 ;
    END
  END xs_q1[151]
  PIN xs_q1[152]
    DIRECTION INPUT ;
    USE SIGNAL ;
    PORT
      LAYER M5 ;
        RECT  281.76 0 281.784 0.084 ;
    END
  END xs_q1[152]
  PIN xs_q1[153]
    DIRECTION INPUT ;
    USE SIGNAL ;
    PORT
      LAYER M5 ;
        RECT  281.856 0 281.88 0.084 ;
    END
  END xs_q1[153]
  PIN xs_q1[154]
    DIRECTION INPUT ;
    USE SIGNAL ;
    PORT
      LAYER M5 ;
        RECT  281.952 0 281.976 0.084 ;
    END
  END xs_q1[154]
  PIN xs_q1[155]
    DIRECTION INPUT ;
    USE SIGNAL ;
    PORT
      LAYER M5 ;
        RECT  282.048 0 282.072 0.084 ;
    END
  END xs_q1[155]
  PIN xs_q1[156]
    DIRECTION INPUT ;
    USE SIGNAL ;
    PORT
      LAYER M5 ;
        RECT  282.144 0 282.168 0.084 ;
    END
  END xs_q1[156]
  PIN xs_q1[157]
    DIRECTION INPUT ;
    USE SIGNAL ;
    PORT
      LAYER M5 ;
        RECT  282.24 0 282.264 0.084 ;
    END
  END xs_q1[157]
  PIN xs_q1[158]
    DIRECTION INPUT ;
    USE SIGNAL ;
    PORT
      LAYER M5 ;
        RECT  282.336 0 282.36 0.084 ;
    END
  END xs_q1[158]
  PIN xs_q1[159]
    DIRECTION INPUT ;
    USE SIGNAL ;
    PORT
      LAYER M5 ;
        RECT  282.432 0 282.456 0.084 ;
    END
  END xs_q1[159]
  PIN xs_q1[15]
    DIRECTION INPUT ;
    USE SIGNAL ;
    PORT
      LAYER M5 ;
        RECT  268.608 0 268.632 0.084 ;
    END
  END xs_q1[15]
  PIN xs_q1[160]
    DIRECTION INPUT ;
    USE SIGNAL ;
    PORT
      LAYER M5 ;
        RECT  282.528 0 282.552 0.084 ;
    END
  END xs_q1[160]
  PIN xs_q1[161]
    DIRECTION INPUT ;
    USE SIGNAL ;
    PORT
      LAYER M5 ;
        RECT  282.624 0 282.648 0.084 ;
    END
  END xs_q1[161]
  PIN xs_q1[162]
    DIRECTION INPUT ;
    USE SIGNAL ;
    PORT
      LAYER M5 ;
        RECT  282.72 0 282.744 0.084 ;
    END
  END xs_q1[162]
  PIN xs_q1[163]
    DIRECTION INPUT ;
    USE SIGNAL ;
    PORT
      LAYER M5 ;
        RECT  282.816 0 282.84 0.084 ;
    END
  END xs_q1[163]
  PIN xs_q1[164]
    DIRECTION INPUT ;
    USE SIGNAL ;
    PORT
      LAYER M5 ;
        RECT  282.912 0 282.936 0.084 ;
    END
  END xs_q1[164]
  PIN xs_q1[165]
    DIRECTION INPUT ;
    USE SIGNAL ;
    PORT
      LAYER M5 ;
        RECT  283.008 0 283.032 0.084 ;
    END
  END xs_q1[165]
  PIN xs_q1[166]
    DIRECTION INPUT ;
    USE SIGNAL ;
    PORT
      LAYER M5 ;
        RECT  283.104 0 283.128 0.084 ;
    END
  END xs_q1[166]
  PIN xs_q1[167]
    DIRECTION INPUT ;
    USE SIGNAL ;
    PORT
      LAYER M5 ;
        RECT  283.2 0 283.224 0.084 ;
    END
  END xs_q1[167]
  PIN xs_q1[168]
    DIRECTION INPUT ;
    USE SIGNAL ;
    PORT
      LAYER M5 ;
        RECT  283.296 0 283.32 0.084 ;
    END
  END xs_q1[168]
  PIN xs_q1[169]
    DIRECTION INPUT ;
    USE SIGNAL ;
    PORT
      LAYER M5 ;
        RECT  283.392 0 283.416 0.084 ;
    END
  END xs_q1[169]
  PIN xs_q1[16]
    DIRECTION INPUT ;
    USE SIGNAL ;
    PORT
      LAYER M5 ;
        RECT  268.704 0 268.728 0.084 ;
    END
  END xs_q1[16]
  PIN xs_q1[170]
    DIRECTION INPUT ;
    USE SIGNAL ;
    PORT
      LAYER M5 ;
        RECT  283.488 0 283.512 0.084 ;
    END
  END xs_q1[170]
  PIN xs_q1[171]
    DIRECTION INPUT ;
    USE SIGNAL ;
    PORT
      LAYER M5 ;
        RECT  283.584 0 283.608 0.084 ;
    END
  END xs_q1[171]
  PIN xs_q1[172]
    DIRECTION INPUT ;
    USE SIGNAL ;
    PORT
      LAYER M5 ;
        RECT  283.68 0 283.704 0.084 ;
    END
  END xs_q1[172]
  PIN xs_q1[173]
    DIRECTION INPUT ;
    USE SIGNAL ;
    PORT
      LAYER M5 ;
        RECT  283.776 0 283.8 0.084 ;
    END
  END xs_q1[173]
  PIN xs_q1[174]
    DIRECTION INPUT ;
    USE SIGNAL ;
    PORT
      LAYER M5 ;
        RECT  283.872 0 283.896 0.084 ;
    END
  END xs_q1[174]
  PIN xs_q1[175]
    DIRECTION INPUT ;
    USE SIGNAL ;
    PORT
      LAYER M5 ;
        RECT  283.968 0 283.992 0.084 ;
    END
  END xs_q1[175]
  PIN xs_q1[176]
    DIRECTION INPUT ;
    USE SIGNAL ;
    PORT
      LAYER M5 ;
        RECT  284.064 0 284.088 0.084 ;
    END
  END xs_q1[176]
  PIN xs_q1[177]
    DIRECTION INPUT ;
    USE SIGNAL ;
    PORT
      LAYER M5 ;
        RECT  284.16 0 284.184 0.084 ;
    END
  END xs_q1[177]
  PIN xs_q1[178]
    DIRECTION INPUT ;
    USE SIGNAL ;
    PORT
      LAYER M5 ;
        RECT  284.256 0 284.28 0.084 ;
    END
  END xs_q1[178]
  PIN xs_q1[179]
    DIRECTION INPUT ;
    USE SIGNAL ;
    PORT
      LAYER M5 ;
        RECT  284.352 0 284.376 0.084 ;
    END
  END xs_q1[179]
  PIN xs_q1[17]
    DIRECTION INPUT ;
    USE SIGNAL ;
    PORT
      LAYER M5 ;
        RECT  268.8 0 268.824 0.084 ;
    END
  END xs_q1[17]
  PIN xs_q1[180]
    DIRECTION INPUT ;
    USE SIGNAL ;
    PORT
      LAYER M5 ;
        RECT  284.448 0 284.472 0.084 ;
    END
  END xs_q1[180]
  PIN xs_q1[181]
    DIRECTION INPUT ;
    USE SIGNAL ;
    PORT
      LAYER M5 ;
        RECT  284.544 0 284.568 0.084 ;
    END
  END xs_q1[181]
  PIN xs_q1[182]
    DIRECTION INPUT ;
    USE SIGNAL ;
    PORT
      LAYER M5 ;
        RECT  284.64 0 284.664 0.084 ;
    END
  END xs_q1[182]
  PIN xs_q1[183]
    DIRECTION INPUT ;
    USE SIGNAL ;
    PORT
      LAYER M5 ;
        RECT  284.736 0 284.76 0.084 ;
    END
  END xs_q1[183]
  PIN xs_q1[184]
    DIRECTION INPUT ;
    USE SIGNAL ;
    PORT
      LAYER M5 ;
        RECT  284.832 0 284.856 0.084 ;
    END
  END xs_q1[184]
  PIN xs_q1[185]
    DIRECTION INPUT ;
    USE SIGNAL ;
    PORT
      LAYER M5 ;
        RECT  284.928 0 284.952 0.084 ;
    END
  END xs_q1[185]
  PIN xs_q1[186]
    DIRECTION INPUT ;
    USE SIGNAL ;
    PORT
      LAYER M5 ;
        RECT  285.024 0 285.048 0.084 ;
    END
  END xs_q1[186]
  PIN xs_q1[187]
    DIRECTION INPUT ;
    USE SIGNAL ;
    PORT
      LAYER M5 ;
        RECT  285.12 0 285.144 0.084 ;
    END
  END xs_q1[187]
  PIN xs_q1[188]
    DIRECTION INPUT ;
    USE SIGNAL ;
    PORT
      LAYER M5 ;
        RECT  285.216 0 285.24 0.084 ;
    END
  END xs_q1[188]
  PIN xs_q1[189]
    DIRECTION INPUT ;
    USE SIGNAL ;
    PORT
      LAYER M5 ;
        RECT  285.312 0 285.336 0.084 ;
    END
  END xs_q1[189]
  PIN xs_q1[18]
    DIRECTION INPUT ;
    USE SIGNAL ;
    PORT
      LAYER M5 ;
        RECT  268.896 0 268.92 0.084 ;
    END
  END xs_q1[18]
  PIN xs_q1[190]
    DIRECTION INPUT ;
    USE SIGNAL ;
    PORT
      LAYER M5 ;
        RECT  285.408 0 285.432 0.084 ;
    END
  END xs_q1[190]
  PIN xs_q1[191]
    DIRECTION INPUT ;
    USE SIGNAL ;
    PORT
      LAYER M5 ;
        RECT  285.504 0 285.528 0.084 ;
    END
  END xs_q1[191]
  PIN xs_q1[192]
    DIRECTION INPUT ;
    USE SIGNAL ;
    PORT
      LAYER M5 ;
        RECT  285.6 0 285.624 0.084 ;
    END
  END xs_q1[192]
  PIN xs_q1[193]
    DIRECTION INPUT ;
    USE SIGNAL ;
    PORT
      LAYER M5 ;
        RECT  285.696 0 285.72 0.084 ;
    END
  END xs_q1[193]
  PIN xs_q1[194]
    DIRECTION INPUT ;
    USE SIGNAL ;
    PORT
      LAYER M5 ;
        RECT  285.792 0 285.816 0.084 ;
    END
  END xs_q1[194]
  PIN xs_q1[195]
    DIRECTION INPUT ;
    USE SIGNAL ;
    PORT
      LAYER M5 ;
        RECT  285.888 0 285.912 0.084 ;
    END
  END xs_q1[195]
  PIN xs_q1[196]
    DIRECTION INPUT ;
    USE SIGNAL ;
    PORT
      LAYER M5 ;
        RECT  285.984 0 286.008 0.084 ;
    END
  END xs_q1[196]
  PIN xs_q1[197]
    DIRECTION INPUT ;
    USE SIGNAL ;
    PORT
      LAYER M5 ;
        RECT  286.08 0 286.104 0.084 ;
    END
  END xs_q1[197]
  PIN xs_q1[198]
    DIRECTION INPUT ;
    USE SIGNAL ;
    PORT
      LAYER M5 ;
        RECT  286.176 0 286.2 0.084 ;
    END
  END xs_q1[198]
  PIN xs_q1[199]
    DIRECTION INPUT ;
    USE SIGNAL ;
    PORT
      LAYER M5 ;
        RECT  286.272 0 286.296 0.084 ;
    END
  END xs_q1[199]
  PIN xs_q1[19]
    DIRECTION INPUT ;
    USE SIGNAL ;
    PORT
      LAYER M5 ;
        RECT  268.992 0 269.016 0.084 ;
    END
  END xs_q1[19]
  PIN xs_q1[1]
    DIRECTION INPUT ;
    USE SIGNAL ;
    PORT
      LAYER M5 ;
        RECT  267.264 0 267.288 0.084 ;
    END
  END xs_q1[1]
  PIN xs_q1[200]
    DIRECTION INPUT ;
    USE SIGNAL ;
    PORT
      LAYER M5 ;
        RECT  286.368 0 286.392 0.084 ;
    END
  END xs_q1[200]
  PIN xs_q1[201]
    DIRECTION INPUT ;
    USE SIGNAL ;
    PORT
      LAYER M5 ;
        RECT  286.464 0 286.488 0.084 ;
    END
  END xs_q1[201]
  PIN xs_q1[202]
    DIRECTION INPUT ;
    USE SIGNAL ;
    PORT
      LAYER M5 ;
        RECT  286.56 0 286.584 0.084 ;
    END
  END xs_q1[202]
  PIN xs_q1[203]
    DIRECTION INPUT ;
    USE SIGNAL ;
    PORT
      LAYER M5 ;
        RECT  286.656 0 286.68 0.084 ;
    END
  END xs_q1[203]
  PIN xs_q1[204]
    DIRECTION INPUT ;
    USE SIGNAL ;
    PORT
      LAYER M5 ;
        RECT  286.752 0 286.776 0.084 ;
    END
  END xs_q1[204]
  PIN xs_q1[205]
    DIRECTION INPUT ;
    USE SIGNAL ;
    PORT
      LAYER M5 ;
        RECT  286.848 0 286.872 0.084 ;
    END
  END xs_q1[205]
  PIN xs_q1[206]
    DIRECTION INPUT ;
    USE SIGNAL ;
    PORT
      LAYER M5 ;
        RECT  286.944 0 286.968 0.084 ;
    END
  END xs_q1[206]
  PIN xs_q1[207]
    DIRECTION INPUT ;
    USE SIGNAL ;
    PORT
      LAYER M5 ;
        RECT  287.04 0 287.064 0.084 ;
    END
  END xs_q1[207]
  PIN xs_q1[208]
    DIRECTION INPUT ;
    USE SIGNAL ;
    PORT
      LAYER M5 ;
        RECT  287.136 0 287.16 0.084 ;
    END
  END xs_q1[208]
  PIN xs_q1[209]
    DIRECTION INPUT ;
    USE SIGNAL ;
    PORT
      LAYER M5 ;
        RECT  287.232 0 287.256 0.084 ;
    END
  END xs_q1[209]
  PIN xs_q1[20]
    DIRECTION INPUT ;
    USE SIGNAL ;
    PORT
      LAYER M5 ;
        RECT  269.088 0 269.112 0.084 ;
    END
  END xs_q1[20]
  PIN xs_q1[210]
    DIRECTION INPUT ;
    USE SIGNAL ;
    PORT
      LAYER M5 ;
        RECT  287.328 0 287.352 0.084 ;
    END
  END xs_q1[210]
  PIN xs_q1[211]
    DIRECTION INPUT ;
    USE SIGNAL ;
    PORT
      LAYER M5 ;
        RECT  287.424 0 287.448 0.084 ;
    END
  END xs_q1[211]
  PIN xs_q1[212]
    DIRECTION INPUT ;
    USE SIGNAL ;
    PORT
      LAYER M5 ;
        RECT  287.52 0 287.544 0.084 ;
    END
  END xs_q1[212]
  PIN xs_q1[213]
    DIRECTION INPUT ;
    USE SIGNAL ;
    PORT
      LAYER M5 ;
        RECT  287.616 0 287.64 0.084 ;
    END
  END xs_q1[213]
  PIN xs_q1[214]
    DIRECTION INPUT ;
    USE SIGNAL ;
    PORT
      LAYER M5 ;
        RECT  287.712 0 287.736 0.084 ;
    END
  END xs_q1[214]
  PIN xs_q1[215]
    DIRECTION INPUT ;
    USE SIGNAL ;
    PORT
      LAYER M5 ;
        RECT  287.808 0 287.832 0.084 ;
    END
  END xs_q1[215]
  PIN xs_q1[216]
    DIRECTION INPUT ;
    USE SIGNAL ;
    PORT
      LAYER M5 ;
        RECT  287.904 0 287.928 0.084 ;
    END
  END xs_q1[216]
  PIN xs_q1[217]
    DIRECTION INPUT ;
    USE SIGNAL ;
    PORT
      LAYER M5 ;
        RECT  288 0 288.024 0.084 ;
    END
  END xs_q1[217]
  PIN xs_q1[218]
    DIRECTION INPUT ;
    USE SIGNAL ;
    PORT
      LAYER M5 ;
        RECT  288.096 0 288.12 0.084 ;
    END
  END xs_q1[218]
  PIN xs_q1[219]
    DIRECTION INPUT ;
    USE SIGNAL ;
    PORT
      LAYER M5 ;
        RECT  288.192 0 288.216 0.084 ;
    END
  END xs_q1[219]
  PIN xs_q1[21]
    DIRECTION INPUT ;
    USE SIGNAL ;
    PORT
      LAYER M5 ;
        RECT  269.184 0 269.208 0.084 ;
    END
  END xs_q1[21]
  PIN xs_q1[220]
    DIRECTION INPUT ;
    USE SIGNAL ;
    PORT
      LAYER M5 ;
        RECT  288.288 0 288.312 0.084 ;
    END
  END xs_q1[220]
  PIN xs_q1[221]
    DIRECTION INPUT ;
    USE SIGNAL ;
    PORT
      LAYER M5 ;
        RECT  288.384 0 288.408 0.084 ;
    END
  END xs_q1[221]
  PIN xs_q1[222]
    DIRECTION INPUT ;
    USE SIGNAL ;
    PORT
      LAYER M5 ;
        RECT  288.48 0 288.504 0.084 ;
    END
  END xs_q1[222]
  PIN xs_q1[223]
    DIRECTION INPUT ;
    USE SIGNAL ;
    PORT
      LAYER M5 ;
        RECT  288.576 0 288.6 0.084 ;
    END
  END xs_q1[223]
  PIN xs_q1[224]
    DIRECTION INPUT ;
    USE SIGNAL ;
    PORT
      LAYER M5 ;
        RECT  288.672 0 288.696 0.084 ;
    END
  END xs_q1[224]
  PIN xs_q1[225]
    DIRECTION INPUT ;
    USE SIGNAL ;
    PORT
      LAYER M5 ;
        RECT  288.768 0 288.792 0.084 ;
    END
  END xs_q1[225]
  PIN xs_q1[226]
    DIRECTION INPUT ;
    USE SIGNAL ;
    PORT
      LAYER M5 ;
        RECT  288.864 0 288.888 0.084 ;
    END
  END xs_q1[226]
  PIN xs_q1[227]
    DIRECTION INPUT ;
    USE SIGNAL ;
    PORT
      LAYER M5 ;
        RECT  288.96 0 288.984 0.084 ;
    END
  END xs_q1[227]
  PIN xs_q1[228]
    DIRECTION INPUT ;
    USE SIGNAL ;
    PORT
      LAYER M5 ;
        RECT  289.056 0 289.08 0.084 ;
    END
  END xs_q1[228]
  PIN xs_q1[229]
    DIRECTION INPUT ;
    USE SIGNAL ;
    PORT
      LAYER M5 ;
        RECT  289.152 0 289.176 0.084 ;
    END
  END xs_q1[229]
  PIN xs_q1[22]
    DIRECTION INPUT ;
    USE SIGNAL ;
    PORT
      LAYER M5 ;
        RECT  269.28 0 269.304 0.084 ;
    END
  END xs_q1[22]
  PIN xs_q1[230]
    DIRECTION INPUT ;
    USE SIGNAL ;
    PORT
      LAYER M5 ;
        RECT  289.248 0 289.272 0.084 ;
    END
  END xs_q1[230]
  PIN xs_q1[231]
    DIRECTION INPUT ;
    USE SIGNAL ;
    PORT
      LAYER M5 ;
        RECT  289.344 0 289.368 0.084 ;
    END
  END xs_q1[231]
  PIN xs_q1[232]
    DIRECTION INPUT ;
    USE SIGNAL ;
    PORT
      LAYER M5 ;
        RECT  289.44 0 289.464 0.084 ;
    END
  END xs_q1[232]
  PIN xs_q1[233]
    DIRECTION INPUT ;
    USE SIGNAL ;
    PORT
      LAYER M5 ;
        RECT  289.536 0 289.56 0.084 ;
    END
  END xs_q1[233]
  PIN xs_q1[234]
    DIRECTION INPUT ;
    USE SIGNAL ;
    PORT
      LAYER M5 ;
        RECT  289.632 0 289.656 0.084 ;
    END
  END xs_q1[234]
  PIN xs_q1[235]
    DIRECTION INPUT ;
    USE SIGNAL ;
    PORT
      LAYER M5 ;
        RECT  289.728 0 289.752 0.084 ;
    END
  END xs_q1[235]
  PIN xs_q1[236]
    DIRECTION INPUT ;
    USE SIGNAL ;
    PORT
      LAYER M5 ;
        RECT  289.824 0 289.848 0.084 ;
    END
  END xs_q1[236]
  PIN xs_q1[237]
    DIRECTION INPUT ;
    USE SIGNAL ;
    PORT
      LAYER M5 ;
        RECT  289.92 0 289.944 0.084 ;
    END
  END xs_q1[237]
  PIN xs_q1[238]
    DIRECTION INPUT ;
    USE SIGNAL ;
    PORT
      LAYER M5 ;
        RECT  290.016 0 290.04 0.084 ;
    END
  END xs_q1[238]
  PIN xs_q1[239]
    DIRECTION INPUT ;
    USE SIGNAL ;
    PORT
      LAYER M5 ;
        RECT  290.112 0 290.136 0.084 ;
    END
  END xs_q1[239]
  PIN xs_q1[23]
    DIRECTION INPUT ;
    USE SIGNAL ;
    PORT
      LAYER M5 ;
        RECT  269.376 0 269.4 0.084 ;
    END
  END xs_q1[23]
  PIN xs_q1[240]
    DIRECTION INPUT ;
    USE SIGNAL ;
    PORT
      LAYER M5 ;
        RECT  290.208 0 290.232 0.084 ;
    END
  END xs_q1[240]
  PIN xs_q1[241]
    DIRECTION INPUT ;
    USE SIGNAL ;
    PORT
      LAYER M5 ;
        RECT  290.304 0 290.328 0.084 ;
    END
  END xs_q1[241]
  PIN xs_q1[242]
    DIRECTION INPUT ;
    USE SIGNAL ;
    PORT
      LAYER M5 ;
        RECT  290.4 0 290.424 0.084 ;
    END
  END xs_q1[242]
  PIN xs_q1[243]
    DIRECTION INPUT ;
    USE SIGNAL ;
    PORT
      LAYER M5 ;
        RECT  290.496 0 290.52 0.084 ;
    END
  END xs_q1[243]
  PIN xs_q1[244]
    DIRECTION INPUT ;
    USE SIGNAL ;
    PORT
      LAYER M5 ;
        RECT  290.592 0 290.616 0.084 ;
    END
  END xs_q1[244]
  PIN xs_q1[245]
    DIRECTION INPUT ;
    USE SIGNAL ;
    PORT
      LAYER M5 ;
        RECT  290.688 0 290.712 0.084 ;
    END
  END xs_q1[245]
  PIN xs_q1[246]
    DIRECTION INPUT ;
    USE SIGNAL ;
    PORT
      LAYER M5 ;
        RECT  290.784 0 290.808 0.084 ;
    END
  END xs_q1[246]
  PIN xs_q1[247]
    DIRECTION INPUT ;
    USE SIGNAL ;
    PORT
      LAYER M5 ;
        RECT  290.88 0 290.904 0.084 ;
    END
  END xs_q1[247]
  PIN xs_q1[248]
    DIRECTION INPUT ;
    USE SIGNAL ;
    PORT
      LAYER M5 ;
        RECT  290.976 0 291 0.084 ;
    END
  END xs_q1[248]
  PIN xs_q1[249]
    DIRECTION INPUT ;
    USE SIGNAL ;
    PORT
      LAYER M5 ;
        RECT  291.072 0 291.096 0.084 ;
    END
  END xs_q1[249]
  PIN xs_q1[24]
    DIRECTION INPUT ;
    USE SIGNAL ;
    PORT
      LAYER M5 ;
        RECT  269.472 0 269.496 0.084 ;
    END
  END xs_q1[24]
  PIN xs_q1[250]
    DIRECTION INPUT ;
    USE SIGNAL ;
    PORT
      LAYER M5 ;
        RECT  291.168 0 291.192 0.084 ;
    END
  END xs_q1[250]
  PIN xs_q1[251]
    DIRECTION INPUT ;
    USE SIGNAL ;
    PORT
      LAYER M5 ;
        RECT  291.264 0 291.288 0.084 ;
    END
  END xs_q1[251]
  PIN xs_q1[252]
    DIRECTION INPUT ;
    USE SIGNAL ;
    PORT
      LAYER M5 ;
        RECT  291.36 0 291.384 0.084 ;
    END
  END xs_q1[252]
  PIN xs_q1[253]
    DIRECTION INPUT ;
    USE SIGNAL ;
    PORT
      LAYER M5 ;
        RECT  291.456 0 291.48 0.084 ;
    END
  END xs_q1[253]
  PIN xs_q1[254]
    DIRECTION INPUT ;
    USE SIGNAL ;
    PORT
      LAYER M5 ;
        RECT  291.552 0 291.576 0.084 ;
    END
  END xs_q1[254]
  PIN xs_q1[255]
    DIRECTION INPUT ;
    USE SIGNAL ;
    PORT
      LAYER M5 ;
        RECT  291.648 0 291.672 0.084 ;
    END
  END xs_q1[255]
  PIN xs_q1[25]
    DIRECTION INPUT ;
    USE SIGNAL ;
    PORT
      LAYER M5 ;
        RECT  269.568 0 269.592 0.084 ;
    END
  END xs_q1[25]
  PIN xs_q1[26]
    DIRECTION INPUT ;
    USE SIGNAL ;
    PORT
      LAYER M5 ;
        RECT  269.664 0 269.688 0.084 ;
    END
  END xs_q1[26]
  PIN xs_q1[27]
    DIRECTION INPUT ;
    USE SIGNAL ;
    PORT
      LAYER M5 ;
        RECT  269.76 0 269.784 0.084 ;
    END
  END xs_q1[27]
  PIN xs_q1[28]
    DIRECTION INPUT ;
    USE SIGNAL ;
    PORT
      LAYER M5 ;
        RECT  269.856 0 269.88 0.084 ;
    END
  END xs_q1[28]
  PIN xs_q1[29]
    DIRECTION INPUT ;
    USE SIGNAL ;
    PORT
      LAYER M5 ;
        RECT  269.952 0 269.976 0.084 ;
    END
  END xs_q1[29]
  PIN xs_q1[2]
    DIRECTION INPUT ;
    USE SIGNAL ;
    PORT
      LAYER M5 ;
        RECT  267.36 0 267.384 0.084 ;
    END
  END xs_q1[2]
  PIN xs_q1[30]
    DIRECTION INPUT ;
    USE SIGNAL ;
    PORT
      LAYER M5 ;
        RECT  270.048 0 270.072 0.084 ;
    END
  END xs_q1[30]
  PIN xs_q1[31]
    DIRECTION INPUT ;
    USE SIGNAL ;
    PORT
      LAYER M5 ;
        RECT  270.144 0 270.168 0.084 ;
    END
  END xs_q1[31]
  PIN xs_q1[32]
    DIRECTION INPUT ;
    USE SIGNAL ;
    PORT
      LAYER M5 ;
        RECT  270.24 0 270.264 0.084 ;
    END
  END xs_q1[32]
  PIN xs_q1[33]
    DIRECTION INPUT ;
    USE SIGNAL ;
    PORT
      LAYER M5 ;
        RECT  270.336 0 270.36 0.084 ;
    END
  END xs_q1[33]
  PIN xs_q1[34]
    DIRECTION INPUT ;
    USE SIGNAL ;
    PORT
      LAYER M5 ;
        RECT  270.432 0 270.456 0.084 ;
    END
  END xs_q1[34]
  PIN xs_q1[35]
    DIRECTION INPUT ;
    USE SIGNAL ;
    PORT
      LAYER M5 ;
        RECT  270.528 0 270.552 0.084 ;
    END
  END xs_q1[35]
  PIN xs_q1[36]
    DIRECTION INPUT ;
    USE SIGNAL ;
    PORT
      LAYER M5 ;
        RECT  270.624 0 270.648 0.084 ;
    END
  END xs_q1[36]
  PIN xs_q1[37]
    DIRECTION INPUT ;
    USE SIGNAL ;
    PORT
      LAYER M5 ;
        RECT  270.72 0 270.744 0.084 ;
    END
  END xs_q1[37]
  PIN xs_q1[38]
    DIRECTION INPUT ;
    USE SIGNAL ;
    PORT
      LAYER M5 ;
        RECT  270.816 0 270.84 0.084 ;
    END
  END xs_q1[38]
  PIN xs_q1[39]
    DIRECTION INPUT ;
    USE SIGNAL ;
    PORT
      LAYER M5 ;
        RECT  270.912 0 270.936 0.084 ;
    END
  END xs_q1[39]
  PIN xs_q1[3]
    DIRECTION INPUT ;
    USE SIGNAL ;
    PORT
      LAYER M5 ;
        RECT  267.456 0 267.48 0.084 ;
    END
  END xs_q1[3]
  PIN xs_q1[40]
    DIRECTION INPUT ;
    USE SIGNAL ;
    PORT
      LAYER M5 ;
        RECT  271.008 0 271.032 0.084 ;
    END
  END xs_q1[40]
  PIN xs_q1[41]
    DIRECTION INPUT ;
    USE SIGNAL ;
    PORT
      LAYER M5 ;
        RECT  271.104 0 271.128 0.084 ;
    END
  END xs_q1[41]
  PIN xs_q1[42]
    DIRECTION INPUT ;
    USE SIGNAL ;
    PORT
      LAYER M5 ;
        RECT  271.2 0 271.224 0.084 ;
    END
  END xs_q1[42]
  PIN xs_q1[43]
    DIRECTION INPUT ;
    USE SIGNAL ;
    PORT
      LAYER M5 ;
        RECT  271.296 0 271.32 0.084 ;
    END
  END xs_q1[43]
  PIN xs_q1[44]
    DIRECTION INPUT ;
    USE SIGNAL ;
    PORT
      LAYER M5 ;
        RECT  271.392 0 271.416 0.084 ;
    END
  END xs_q1[44]
  PIN xs_q1[45]
    DIRECTION INPUT ;
    USE SIGNAL ;
    PORT
      LAYER M5 ;
        RECT  271.488 0 271.512 0.084 ;
    END
  END xs_q1[45]
  PIN xs_q1[46]
    DIRECTION INPUT ;
    USE SIGNAL ;
    PORT
      LAYER M5 ;
        RECT  271.584 0 271.608 0.084 ;
    END
  END xs_q1[46]
  PIN xs_q1[47]
    DIRECTION INPUT ;
    USE SIGNAL ;
    PORT
      LAYER M5 ;
        RECT  271.68 0 271.704 0.084 ;
    END
  END xs_q1[47]
  PIN xs_q1[48]
    DIRECTION INPUT ;
    USE SIGNAL ;
    PORT
      LAYER M5 ;
        RECT  271.776 0 271.8 0.084 ;
    END
  END xs_q1[48]
  PIN xs_q1[49]
    DIRECTION INPUT ;
    USE SIGNAL ;
    PORT
      LAYER M5 ;
        RECT  271.872 0 271.896 0.084 ;
    END
  END xs_q1[49]
  PIN xs_q1[4]
    DIRECTION INPUT ;
    USE SIGNAL ;
    PORT
      LAYER M5 ;
        RECT  267.552 0 267.576 0.084 ;
    END
  END xs_q1[4]
  PIN xs_q1[50]
    DIRECTION INPUT ;
    USE SIGNAL ;
    PORT
      LAYER M5 ;
        RECT  271.968 0 271.992 0.084 ;
    END
  END xs_q1[50]
  PIN xs_q1[51]
    DIRECTION INPUT ;
    USE SIGNAL ;
    PORT
      LAYER M5 ;
        RECT  272.064 0 272.088 0.084 ;
    END
  END xs_q1[51]
  PIN xs_q1[52]
    DIRECTION INPUT ;
    USE SIGNAL ;
    PORT
      LAYER M5 ;
        RECT  272.16 0 272.184 0.084 ;
    END
  END xs_q1[52]
  PIN xs_q1[53]
    DIRECTION INPUT ;
    USE SIGNAL ;
    PORT
      LAYER M5 ;
        RECT  272.256 0 272.28 0.084 ;
    END
  END xs_q1[53]
  PIN xs_q1[54]
    DIRECTION INPUT ;
    USE SIGNAL ;
    PORT
      LAYER M5 ;
        RECT  272.352 0 272.376 0.084 ;
    END
  END xs_q1[54]
  PIN xs_q1[55]
    DIRECTION INPUT ;
    USE SIGNAL ;
    PORT
      LAYER M5 ;
        RECT  272.448 0 272.472 0.084 ;
    END
  END xs_q1[55]
  PIN xs_q1[56]
    DIRECTION INPUT ;
    USE SIGNAL ;
    PORT
      LAYER M5 ;
        RECT  272.544 0 272.568 0.084 ;
    END
  END xs_q1[56]
  PIN xs_q1[57]
    DIRECTION INPUT ;
    USE SIGNAL ;
    PORT
      LAYER M5 ;
        RECT  272.64 0 272.664 0.084 ;
    END
  END xs_q1[57]
  PIN xs_q1[58]
    DIRECTION INPUT ;
    USE SIGNAL ;
    PORT
      LAYER M5 ;
        RECT  272.736 0 272.76 0.084 ;
    END
  END xs_q1[58]
  PIN xs_q1[59]
    DIRECTION INPUT ;
    USE SIGNAL ;
    PORT
      LAYER M5 ;
        RECT  272.832 0 272.856 0.084 ;
    END
  END xs_q1[59]
  PIN xs_q1[5]
    DIRECTION INPUT ;
    USE SIGNAL ;
    PORT
      LAYER M5 ;
        RECT  267.648 0 267.672 0.084 ;
    END
  END xs_q1[5]
  PIN xs_q1[60]
    DIRECTION INPUT ;
    USE SIGNAL ;
    PORT
      LAYER M5 ;
        RECT  272.928 0 272.952 0.084 ;
    END
  END xs_q1[60]
  PIN xs_q1[61]
    DIRECTION INPUT ;
    USE SIGNAL ;
    PORT
      LAYER M5 ;
        RECT  273.024 0 273.048 0.084 ;
    END
  END xs_q1[61]
  PIN xs_q1[62]
    DIRECTION INPUT ;
    USE SIGNAL ;
    PORT
      LAYER M5 ;
        RECT  273.12 0 273.144 0.084 ;
    END
  END xs_q1[62]
  PIN xs_q1[63]
    DIRECTION INPUT ;
    USE SIGNAL ;
    PORT
      LAYER M5 ;
        RECT  273.216 0 273.24 0.084 ;
    END
  END xs_q1[63]
  PIN xs_q1[64]
    DIRECTION INPUT ;
    USE SIGNAL ;
    PORT
      LAYER M5 ;
        RECT  273.312 0 273.336 0.084 ;
    END
  END xs_q1[64]
  PIN xs_q1[65]
    DIRECTION INPUT ;
    USE SIGNAL ;
    PORT
      LAYER M5 ;
        RECT  273.408 0 273.432 0.084 ;
    END
  END xs_q1[65]
  PIN xs_q1[66]
    DIRECTION INPUT ;
    USE SIGNAL ;
    PORT
      LAYER M5 ;
        RECT  273.504 0 273.528 0.084 ;
    END
  END xs_q1[66]
  PIN xs_q1[67]
    DIRECTION INPUT ;
    USE SIGNAL ;
    PORT
      LAYER M5 ;
        RECT  273.6 0 273.624 0.084 ;
    END
  END xs_q1[67]
  PIN xs_q1[68]
    DIRECTION INPUT ;
    USE SIGNAL ;
    PORT
      LAYER M5 ;
        RECT  273.696 0 273.72 0.084 ;
    END
  END xs_q1[68]
  PIN xs_q1[69]
    DIRECTION INPUT ;
    USE SIGNAL ;
    PORT
      LAYER M5 ;
        RECT  273.792 0 273.816 0.084 ;
    END
  END xs_q1[69]
  PIN xs_q1[6]
    DIRECTION INPUT ;
    USE SIGNAL ;
    PORT
      LAYER M5 ;
        RECT  267.744 0 267.768 0.084 ;
    END
  END xs_q1[6]
  PIN xs_q1[70]
    DIRECTION INPUT ;
    USE SIGNAL ;
    PORT
      LAYER M5 ;
        RECT  273.888 0 273.912 0.084 ;
    END
  END xs_q1[70]
  PIN xs_q1[71]
    DIRECTION INPUT ;
    USE SIGNAL ;
    PORT
      LAYER M5 ;
        RECT  273.984 0 274.008 0.084 ;
    END
  END xs_q1[71]
  PIN xs_q1[72]
    DIRECTION INPUT ;
    USE SIGNAL ;
    PORT
      LAYER M5 ;
        RECT  274.08 0 274.104 0.084 ;
    END
  END xs_q1[72]
  PIN xs_q1[73]
    DIRECTION INPUT ;
    USE SIGNAL ;
    PORT
      LAYER M5 ;
        RECT  274.176 0 274.2 0.084 ;
    END
  END xs_q1[73]
  PIN xs_q1[74]
    DIRECTION INPUT ;
    USE SIGNAL ;
    PORT
      LAYER M5 ;
        RECT  274.272 0 274.296 0.084 ;
    END
  END xs_q1[74]
  PIN xs_q1[75]
    DIRECTION INPUT ;
    USE SIGNAL ;
    PORT
      LAYER M5 ;
        RECT  274.368 0 274.392 0.084 ;
    END
  END xs_q1[75]
  PIN xs_q1[76]
    DIRECTION INPUT ;
    USE SIGNAL ;
    PORT
      LAYER M5 ;
        RECT  274.464 0 274.488 0.084 ;
    END
  END xs_q1[76]
  PIN xs_q1[77]
    DIRECTION INPUT ;
    USE SIGNAL ;
    PORT
      LAYER M5 ;
        RECT  274.56 0 274.584 0.084 ;
    END
  END xs_q1[77]
  PIN xs_q1[78]
    DIRECTION INPUT ;
    USE SIGNAL ;
    PORT
      LAYER M5 ;
        RECT  274.656 0 274.68 0.084 ;
    END
  END xs_q1[78]
  PIN xs_q1[79]
    DIRECTION INPUT ;
    USE SIGNAL ;
    PORT
      LAYER M5 ;
        RECT  274.752 0 274.776 0.084 ;
    END
  END xs_q1[79]
  PIN xs_q1[7]
    DIRECTION INPUT ;
    USE SIGNAL ;
    PORT
      LAYER M5 ;
        RECT  267.84 0 267.864 0.084 ;
    END
  END xs_q1[7]
  PIN xs_q1[80]
    DIRECTION INPUT ;
    USE SIGNAL ;
    PORT
      LAYER M5 ;
        RECT  274.848 0 274.872 0.084 ;
    END
  END xs_q1[80]
  PIN xs_q1[81]
    DIRECTION INPUT ;
    USE SIGNAL ;
    PORT
      LAYER M5 ;
        RECT  274.944 0 274.968 0.084 ;
    END
  END xs_q1[81]
  PIN xs_q1[82]
    DIRECTION INPUT ;
    USE SIGNAL ;
    PORT
      LAYER M5 ;
        RECT  275.04 0 275.064 0.084 ;
    END
  END xs_q1[82]
  PIN xs_q1[83]
    DIRECTION INPUT ;
    USE SIGNAL ;
    PORT
      LAYER M5 ;
        RECT  275.136 0 275.16 0.084 ;
    END
  END xs_q1[83]
  PIN xs_q1[84]
    DIRECTION INPUT ;
    USE SIGNAL ;
    PORT
      LAYER M5 ;
        RECT  275.232 0 275.256 0.084 ;
    END
  END xs_q1[84]
  PIN xs_q1[85]
    DIRECTION INPUT ;
    USE SIGNAL ;
    PORT
      LAYER M5 ;
        RECT  275.328 0 275.352 0.084 ;
    END
  END xs_q1[85]
  PIN xs_q1[86]
    DIRECTION INPUT ;
    USE SIGNAL ;
    PORT
      LAYER M5 ;
        RECT  275.424 0 275.448 0.084 ;
    END
  END xs_q1[86]
  PIN xs_q1[87]
    DIRECTION INPUT ;
    USE SIGNAL ;
    PORT
      LAYER M5 ;
        RECT  275.52 0 275.544 0.084 ;
    END
  END xs_q1[87]
  PIN xs_q1[88]
    DIRECTION INPUT ;
    USE SIGNAL ;
    PORT
      LAYER M5 ;
        RECT  275.616 0 275.64 0.084 ;
    END
  END xs_q1[88]
  PIN xs_q1[89]
    DIRECTION INPUT ;
    USE SIGNAL ;
    PORT
      LAYER M5 ;
        RECT  275.712 0 275.736 0.084 ;
    END
  END xs_q1[89]
  PIN xs_q1[8]
    DIRECTION INPUT ;
    USE SIGNAL ;
    PORT
      LAYER M5 ;
        RECT  267.936 0 267.96 0.084 ;
    END
  END xs_q1[8]
  PIN xs_q1[90]
    DIRECTION INPUT ;
    USE SIGNAL ;
    PORT
      LAYER M5 ;
        RECT  275.808 0 275.832 0.084 ;
    END
  END xs_q1[90]
  PIN xs_q1[91]
    DIRECTION INPUT ;
    USE SIGNAL ;
    PORT
      LAYER M5 ;
        RECT  275.904 0 275.928 0.084 ;
    END
  END xs_q1[91]
  PIN xs_q1[92]
    DIRECTION INPUT ;
    USE SIGNAL ;
    PORT
      LAYER M5 ;
        RECT  276 0 276.024 0.084 ;
    END
  END xs_q1[92]
  PIN xs_q1[93]
    DIRECTION INPUT ;
    USE SIGNAL ;
    PORT
      LAYER M5 ;
        RECT  276.096 0 276.12 0.084 ;
    END
  END xs_q1[93]
  PIN xs_q1[94]
    DIRECTION INPUT ;
    USE SIGNAL ;
    PORT
      LAYER M5 ;
        RECT  276.192 0 276.216 0.084 ;
    END
  END xs_q1[94]
  PIN xs_q1[95]
    DIRECTION INPUT ;
    USE SIGNAL ;
    PORT
      LAYER M5 ;
        RECT  276.288 0 276.312 0.084 ;
    END
  END xs_q1[95]
  PIN xs_q1[96]
    DIRECTION INPUT ;
    USE SIGNAL ;
    PORT
      LAYER M5 ;
        RECT  276.384 0 276.408 0.084 ;
    END
  END xs_q1[96]
  PIN xs_q1[97]
    DIRECTION INPUT ;
    USE SIGNAL ;
    PORT
      LAYER M5 ;
        RECT  276.48 0 276.504 0.084 ;
    END
  END xs_q1[97]
  PIN xs_q1[98]
    DIRECTION INPUT ;
    USE SIGNAL ;
    PORT
      LAYER M5 ;
        RECT  276.576 0 276.6 0.084 ;
    END
  END xs_q1[98]
  PIN xs_q1[99]
    DIRECTION INPUT ;
    USE SIGNAL ;
    PORT
      LAYER M5 ;
        RECT  276.672 0 276.696 0.084 ;
    END
  END xs_q1[99]
  PIN xs_q1[9]
    DIRECTION INPUT ;
    USE SIGNAL ;
    PORT
      LAYER M5 ;
        RECT  268.032 0 268.056 0.084 ;
    END
  END xs_q1[9]
  PIN xs_sv[0]
    DIRECTION INPUT ;
    USE SIGNAL ;
    PORT
      LAYER M5 ;
        RECT  291.744 0 291.768 0.084 ;
    END
  END xs_sv[0]
  PIN xs_sv[1]
    DIRECTION INPUT ;
    USE SIGNAL ;
    PORT
      LAYER M5 ;
        RECT  291.84 0 291.864 0.084 ;
    END
  END xs_sv[1]
  PIN xs_v
    DIRECTION INPUT ;
    USE SIGNAL ;
    PORT
      LAYER M5 ;
        RECT  291.936 0 291.96 0.084 ;
    END
  END xs_v
  PIN VDD
    DIRECTION INOUT ;
    USE POWER ;
    PORT
      LAYER M6 ;
        RECT  2.16 127.113 511.596 127.401 ;
        RECT  2.16 121.713 511.596 122.001 ;
        RECT  2.16 116.313 511.596 116.601 ;
        RECT  2.16 110.913 511.596 111.201 ;
        RECT  2.16 105.513 511.596 105.801 ;
        RECT  2.16 100.113 511.596 100.401 ;
        RECT  2.16 94.713 511.596 95.001 ;
        RECT  2.16 89.313 511.596 89.601 ;
        RECT  2.16 83.913 511.596 84.201 ;
        RECT  2.16 78.513 511.596 78.801 ;
        RECT  2.16 73.113 511.596 73.401 ;
        RECT  2.16 67.713 511.596 68.001 ;
        RECT  2.16 62.313 511.596 62.601 ;
        RECT  2.16 56.913 511.596 57.201 ;
        RECT  2.16 51.513 511.596 51.801 ;
        RECT  2.16 46.113 511.596 46.401 ;
        RECT  2.16 40.713 511.596 41.001 ;
        RECT  2.16 35.313 511.596 35.601 ;
        RECT  2.16 29.913 511.596 30.201 ;
        RECT  2.16 24.513 511.596 24.801 ;
        RECT  2.16 19.113 511.596 19.401 ;
        RECT  2.16 13.713 511.596 14.001 ;
        RECT  2.16 8.313 511.596 8.601 ;
        RECT  2.16 2.913 511.596 3.201 ;
    END
  END VDD
  PIN VSS
    DIRECTION INOUT ;
    USE GROUND ;
    PORT
      LAYER M6 ;
        RECT  2.16 126.729 511.596 127.017 ;
        RECT  2.16 121.329 511.596 121.617 ;
        RECT  2.16 115.929 511.596 116.217 ;
        RECT  2.16 110.529 511.596 110.817 ;
        RECT  2.16 105.129 511.596 105.417 ;
        RECT  2.16 99.729 511.596 100.017 ;
        RECT  2.16 94.329 511.596 94.617 ;
        RECT  2.16 88.929 511.596 89.217 ;
        RECT  2.16 83.529 511.596 83.817 ;
        RECT  2.16 78.129 511.596 78.417 ;
        RECT  2.16 72.729 511.596 73.017 ;
        RECT  2.16 67.329 511.596 67.617 ;
        RECT  2.16 61.929 511.596 62.217 ;
        RECT  2.16 56.529 511.596 56.817 ;
        RECT  2.16 51.129 511.596 51.417 ;
        RECT  2.16 45.729 511.596 46.017 ;
        RECT  2.16 40.329 511.596 40.617 ;
        RECT  2.16 34.929 511.596 35.217 ;
        RECT  2.16 29.529 511.596 29.817 ;
        RECT  2.16 24.129 511.596 24.417 ;
        RECT  2.16 18.729 511.596 19.017 ;
        RECT  2.16 13.329 511.596 13.617 ;
        RECT  2.16 7.929 511.596 8.217 ;
        RECT  2.16 2.529 511.596 2.817 ;
    END
  END VSS
  OBS
    LAYER RVTN ;
     RECT  2.16 0 511.596 130.001 ;
    LAYER RVTP ;
     RECT  2.16 0 511.596 130.001 ;
    LAYER M1 ;
     RECT  2.16 0 511.596 130.001 ;
    LAYER M2 ;
     RECT  2.16 0 511.596 130.001 ;
    LAYER M3 ;
     RECT  2.16 0 511.596 130.001 ;
    LAYER M4 ;
     RECT  2.16 0 511.596 130.001 ;
    LAYER M5 ;
     RECT  2.16 0 511.596 130.001 ;
    LAYER M6 ;
     RECT  2.16 0 511.596 130.001 ;
    LAYER M7 ;
     RECT  2.16 0 511.596 130.001 ;
  END
END ot_v41_rom_elem_q
END LIBRARY
